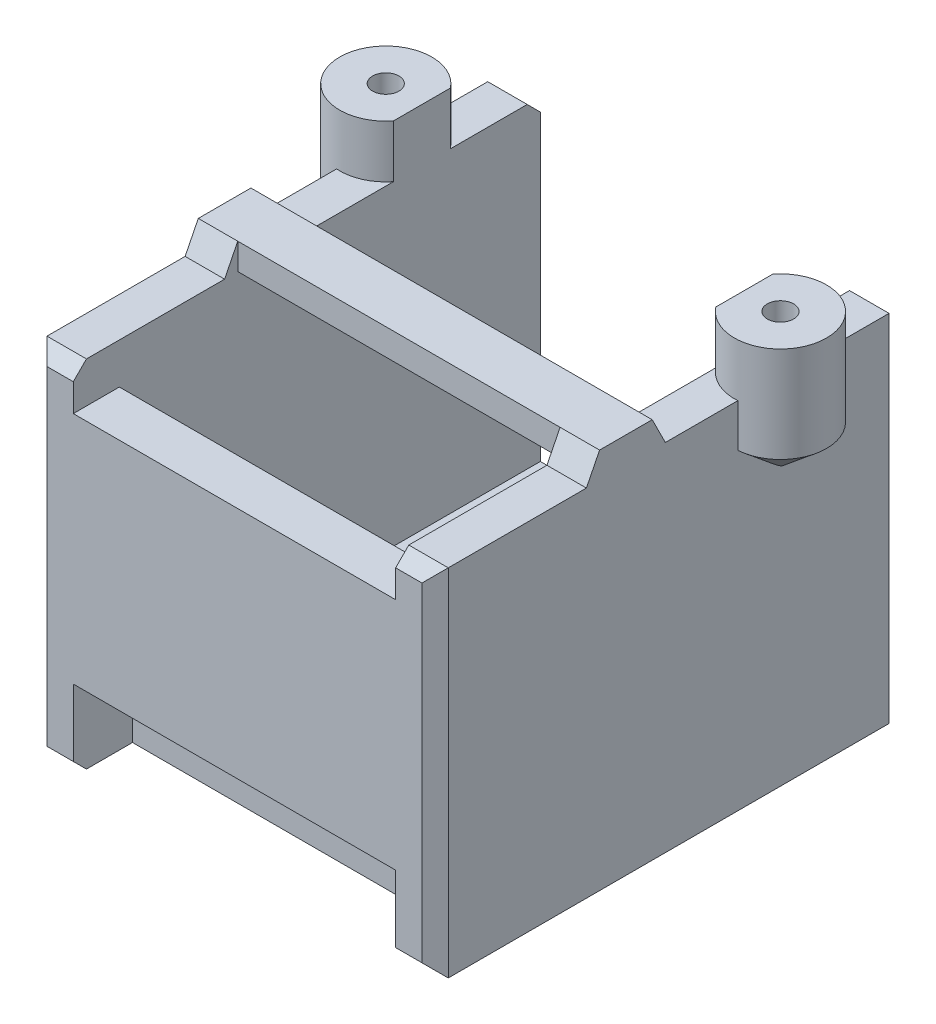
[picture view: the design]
ISO-10303-21;
HEADER;
FILE_DESCRIPTION(('STEP AP214'),'2;1');
FILE_NAME('part.step','',(''),(''),'','','');
FILE_SCHEMA(('AUTOMOTIVE_DESIGN { 1 0 10303 214 1 1 1 1 }'));
ENDSEC;
DATA;
#1=APPLICATION_CONTEXT('core data for automotive mechanical design processes');
#2=APPLICATION_PROTOCOL_DEFINITION('international standard','automotive_design',2000,#1);
#3=PRODUCT_CONTEXT('',#1,'mechanical');
#4=PRODUCT('Part','Part','',(#3));
#5=PRODUCT_RELATED_PRODUCT_CATEGORY('part','',(#4));
#6=PRODUCT_DEFINITION_FORMATION('','',#4);
#7=PRODUCT_DEFINITION_CONTEXT('part definition',#1,'design');
#8=PRODUCT_DEFINITION('design','',#6,#7);
#9=PRODUCT_DEFINITION_SHAPE('','',#8);
#10=(LENGTH_UNIT() NAMED_UNIT(*) SI_UNIT(.MILLI.,.METRE.));
#11=(NAMED_UNIT(*) PLANE_ANGLE_UNIT() SI_UNIT($,.RADIAN.));
#12=(NAMED_UNIT(*) SI_UNIT($,.STERADIAN.) SOLID_ANGLE_UNIT());
#13=UNCERTAINTY_MEASURE_WITH_UNIT(LENGTH_MEASURE(1.E-05),#10,'distance_accuracy_value','');
#14=(GEOMETRIC_REPRESENTATION_CONTEXT(3) GLOBAL_UNCERTAINTY_ASSIGNED_CONTEXT((#13)) GLOBAL_UNIT_ASSIGNED_CONTEXT((#10,
#11,#12)) REPRESENTATION_CONTEXT('',''));
#15=CARTESIAN_POINT('',(0.,0.,0.));
#16=DIRECTION('',(0.,0.,1.));
#17=DIRECTION('',(1.,0.,0.));
#18=AXIS2_PLACEMENT_3D('',#15,#16,#17);
#19=CARTESIAN_POINT('',(0.,12.,0.));
#20=DIRECTION('',(0.,1.,0.));
#21=DIRECTION('',(0.,0.,1.));
#22=AXIS2_PLACEMENT_3D('',#19,#20,#21);
#23=PLANE('',#22);
#24=DIRECTION('',(0.,0.,-1.));
#25=VECTOR('',#24,1.);
#26=CARTESIAN_POINT('',(15.25,12.,0.));
#27=LINE('',#26,#25);
#28=CARTESIAN_POINT('',(15.25,12.,19.));
#29=VERTEX_POINT('',#28);
#30=CARTESIAN_POINT('',(15.25,12.,8.5));
#31=VERTEX_POINT('',#30);
#32=EDGE_CURVE('E683',#29,#31,#27,.T.);
#33=ORIENTED_EDGE('',*,*,#32,.T.);
#34=DIRECTION('',(-1.,0.,0.));
#35=VECTOR('',#34,1.);
#36=CARTESIAN_POINT('',(0.,12.,8.5));
#37=LINE('',#36,#35);
#38=CARTESIAN_POINT('',(12.25,12.,8.5));
#39=VERTEX_POINT('',#38);
#40=EDGE_CURVE('E375',#31,#39,#37,.T.);
#41=ORIENTED_EDGE('',*,*,#40,.T.);
#42=DIRECTION('',(0.,0.,-1.));
#43=VECTOR('',#42,1.);
#44=CARTESIAN_POINT('',(12.25,12.,0.));
#45=LINE('',#44,#43);
#46=CARTESIAN_POINT('',(12.25,12.,19.));
#47=VERTEX_POINT('',#46);
#48=EDGE_CURVE('E681',#47,#39,#45,.T.);
#49=ORIENTED_EDGE('',*,*,#48,.F.);
#50=DIRECTION('',(1.,0.,0.));
#51=VECTOR('',#50,1.);
#52=CARTESIAN_POINT('',(15.25,12.,19.));
#53=LINE('',#52,#51);
#54=EDGE_CURVE('E450',#47,#29,#53,.T.);
#55=ORIENTED_EDGE('',*,*,#54,.T.);
#56=EDGE_LOOP('',(#33,#41,#49,#55));
#57=FACE_BOUND('',#56,.T.);
#58=ADVANCED_FACE('F41',(#57),#23,.T.);
#59=CARTESIAN_POINT('',(12.25,12.,2.5));
#60=VERTEX_POINT('',#59);
#61=CARTESIAN_POINT('',(12.25,12.,-4.33493649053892));
#62=VERTEX_POINT('',#61);
#63=EDGE_CURVE('E769',#60,#62,#45,.T.);
#64=ORIENTED_EDGE('',*,*,#63,.F.);
#65=DIRECTION('',(1.,0.,0.));
#66=VECTOR('',#65,1.);
#67=CARTESIAN_POINT('',(0.,12.,2.5));
#68=LINE('',#67,#66);
#69=CARTESIAN_POINT('',(15.25,12.,2.5));
#70=VERTEX_POINT('',#69);
#71=EDGE_CURVE('E402',#60,#70,#68,.T.);
#72=ORIENTED_EDGE('',*,*,#71,.T.);
#73=CARTESIAN_POINT('',(15.25,12.,-3.00893998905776));
#74=VERTEX_POINT('',#73);
#75=EDGE_CURVE('E367',#70,#74,#27,.T.);
#76=ORIENTED_EDGE('',*,*,#75,.T.);
#77=CARTESIAN_POINT('',(15.,12.,-6.5));
#78=DIRECTION('',(0.,1.,0.));
#79=DIRECTION('',(0.,0.,1.));
#80=AXIS2_PLACEMENT_3D('',#77,#78,#79);
#81=CIRCLE('',#80,3.5);
#82=EDGE_CURVE('E1433',#62,#74,#81,.T.);
#83=ORIENTED_EDGE('',*,*,#82,.F.);
#84=EDGE_LOOP('',(#64,#72,#76,#83));
#85=FACE_BOUND('',#84,.T.);
#86=ADVANCED_FACE('F651',(#85),#23,.T.);
#87=CARTESIAN_POINT('',(0.,12.,0.));
#88=DIRECTION('',(0.,1.,0.));
#89=DIRECTION('',(0.,0.,1.));
#90=AXIS2_PLACEMENT_3D('',#87,#88,#89);
#91=PLANE('',#90);
#92=DIRECTION('',(0.,0.,1.));
#93=VECTOR('',#92,1.);
#94=CARTESIAN_POINT('',(-12.25,12.,0.));
#95=LINE('',#94,#93);
#96=CARTESIAN_POINT('',(-12.25,12.,8.49999999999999));
#97=VERTEX_POINT('',#96);
#98=CARTESIAN_POINT('',(-12.25,12.,19.));
#99=VERTEX_POINT('',#98);
#100=EDGE_CURVE('E383',#97,#99,#95,.T.);
#101=ORIENTED_EDGE('',*,*,#100,.F.);
#102=DIRECTION('',(-1.,0.,0.));
#103=VECTOR('',#102,1.);
#104=CARTESIAN_POINT('',(0.,12.,8.49999999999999));
#105=LINE('',#104,#103);
#106=CARTESIAN_POINT('',(-15.25,12.,8.49999999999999));
#107=VERTEX_POINT('',#106);
#108=EDGE_CURVE('E388',#97,#107,#105,.T.);
#109=ORIENTED_EDGE('',*,*,#108,.T.);
#110=DIRECTION('',(0.,0.,1.));
#111=VECTOR('',#110,1.);
#112=CARTESIAN_POINT('',(-15.25,12.,0.));
#113=LINE('',#112,#111);
#114=CARTESIAN_POINT('',(-15.25,12.,19.));
#115=VERTEX_POINT('',#114);
#116=EDGE_CURVE('E325',#107,#115,#113,.T.);
#117=ORIENTED_EDGE('',*,*,#116,.T.);
#118=DIRECTION('',(1.,0.,0.));
#119=VECTOR('',#118,1.);
#120=CARTESIAN_POINT('',(-12.25,12.,19.));
#121=LINE('',#120,#119);
#122=EDGE_CURVE('E390',#115,#99,#121,.T.);
#123=ORIENTED_EDGE('',*,*,#122,.T.);
#124=EDGE_LOOP('',(#101,#109,#117,#123));
#125=FACE_BOUND('',#124,.T.);
#126=ADVANCED_FACE('F387',(#125),#91,.T.);
#127=CARTESIAN_POINT('',(-15.25,12.,-3.00893998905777));
#128=VERTEX_POINT('',#127);
#129=CARTESIAN_POINT('',(-15.25,12.,2.5));
#130=VERTEX_POINT('',#129);
#131=EDGE_CURVE('E712',#128,#130,#113,.T.);
#132=ORIENTED_EDGE('',*,*,#131,.T.);
#133=DIRECTION('',(1.,0.,0.));
#134=VECTOR('',#133,1.);
#135=CARTESIAN_POINT('',(0.,12.,2.5));
#136=LINE('',#135,#134);
#137=CARTESIAN_POINT('',(-12.25,12.,2.5));
#138=VERTEX_POINT('',#137);
#139=EDGE_CURVE('E400',#130,#138,#136,.T.);
#140=ORIENTED_EDGE('',*,*,#139,.T.);
#141=CARTESIAN_POINT('',(-12.25,12.,-4.33493649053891));
#142=VERTEX_POINT('',#141);
#143=EDGE_CURVE('E392',#142,#138,#95,.T.);
#144=ORIENTED_EDGE('',*,*,#143,.F.);
#145=CARTESIAN_POINT('',(-15.,12.,-6.5));
#146=DIRECTION('',(0.,1.,0.));
#147=DIRECTION('',(0.,0.,1.));
#148=AXIS2_PLACEMENT_3D('',#145,#146,#147);
#149=CIRCLE('',#148,3.5);
#150=EDGE_CURVE('E830',#128,#142,#149,.T.);
#151=ORIENTED_EDGE('',*,*,#150,.F.);
#152=EDGE_LOOP('',(#132,#140,#144,#151));
#153=FACE_BOUND('',#152,.T.);
#154=ADVANCED_FACE('F663',(#153),#91,.T.);
#155=CARTESIAN_POINT('',(15.25,12.,-9.99106001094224));
#156=VERTEX_POINT('',#155);
#157=CARTESIAN_POINT('',(15.25,12.,-14.5));
#158=VERTEX_POINT('',#157);
#159=EDGE_CURVE('E675',#156,#158,#27,.T.);
#160=ORIENTED_EDGE('',*,*,#159,.T.);
#161=DIRECTION('',(-1.,0.,0.));
#162=VECTOR('',#161,1.);
#163=CARTESIAN_POINT('',(12.25,12.,-14.5));
#164=LINE('',#163,#162);
#165=CARTESIAN_POINT('',(12.25,12.,-14.5));
#166=VERTEX_POINT('',#165);
#167=EDGE_CURVE('E472',#158,#166,#164,.T.);
#168=ORIENTED_EDGE('',*,*,#167,.T.);
#169=CARTESIAN_POINT('',(12.25,12.,-8.66506350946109));
#170=VERTEX_POINT('',#169);
#171=EDGE_CURVE('E766',#170,#166,#45,.T.);
#172=ORIENTED_EDGE('',*,*,#171,.F.);
#173=EDGE_CURVE('E679',#156,#170,#81,.T.);
#174=ORIENTED_EDGE('',*,*,#173,.F.);
#175=EDGE_LOOP('',(#160,#168,#172,#174));
#176=FACE_BOUND('',#175,.T.);
#177=ADVANCED_FACE('F654',(#176),#23,.T.);
#178=CARTESIAN_POINT('',(-12.25,12.,-14.5));
#179=VERTEX_POINT('',#178);
#180=CARTESIAN_POINT('',(-12.25,12.,-8.66506350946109));
#181=VERTEX_POINT('',#180);
#182=EDGE_CURVE('E395',#179,#181,#95,.T.);
#183=ORIENTED_EDGE('',*,*,#182,.F.);
#184=DIRECTION('',(-1.,0.,0.));
#185=VECTOR('',#184,1.);
#186=CARTESIAN_POINT('',(-15.25,12.,-14.5));
#187=LINE('',#186,#185);
#188=CARTESIAN_POINT('',(-15.25,12.,-14.5));
#189=VERTEX_POINT('',#188);
#190=EDGE_CURVE('E504',#179,#189,#187,.T.);
#191=ORIENTED_EDGE('',*,*,#190,.T.);
#192=CARTESIAN_POINT('',(-15.25,12.,-9.99106001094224));
#193=VERTEX_POINT('',#192);
#194=EDGE_CURVE('E709',#189,#193,#113,.T.);
#195=ORIENTED_EDGE('',*,*,#194,.T.);
#196=EDGE_CURVE('E836',#181,#193,#149,.T.);
#197=ORIENTED_EDGE('',*,*,#196,.F.);
#198=EDGE_LOOP('',(#183,#191,#195,#197));
#199=FACE_BOUND('',#198,.T.);
#200=ADVANCED_FACE('F662',(#199),#91,.T.);
#201=CARTESIAN_POINT('',(0.,8.9,15.5));
#202=DIRECTION('',(0.,0.,-1.));
#203=DIRECTION('',(-1.,0.,0.));
#204=AXIS2_PLACEMENT_3D('',#201,#202,#203);
#205=PLANE('',#204);
#206=DIRECTION('',(0.,-1.,0.));
#207=VECTOR('',#206,1.);
#208=CARTESIAN_POINT('',(12.25,8.9,15.5));
#209=LINE('',#208,#207);
#210=CARTESIAN_POINT('',(12.25,7.90000000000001,15.5));
#211=VERTEX_POINT('',#210);
#212=CARTESIAN_POINT('',(12.25,-7.9,15.5));
#213=VERTEX_POINT('',#212);
#214=EDGE_CURVE('E736',#211,#213,#209,.T.);
#215=ORIENTED_EDGE('',*,*,#214,.T.);
#216=DIRECTION('',(-1.,0.,0.));
#217=VECTOR('',#216,1.);
#218=CARTESIAN_POINT('',(-12.25,-7.9,15.5));
#219=LINE('',#218,#217);
#220=CARTESIAN_POINT('',(-12.25,-7.9,15.5));
#221=VERTEX_POINT('',#220);
#222=EDGE_CURVE('E417',#213,#221,#219,.T.);
#223=ORIENTED_EDGE('',*,*,#222,.T.);
#224=DIRECTION('',(0.,-1.,0.));
#225=VECTOR('',#224,1.);
#226=CARTESIAN_POINT('',(-12.25,8.9,15.5));
#227=LINE('',#226,#225);
#228=CARTESIAN_POINT('',(-12.25,7.90000000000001,15.5));
#229=VERTEX_POINT('',#228);
#230=EDGE_CURVE('E728',#229,#221,#227,.T.);
#231=ORIENTED_EDGE('',*,*,#230,.F.);
#232=DIRECTION('',(1.,0.,0.));
#233=VECTOR('',#232,1.);
#234=CARTESIAN_POINT('',(0.,7.90000000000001,15.5));
#235=LINE('',#234,#233);
#236=EDGE_CURVE('E419',#229,#211,#235,.T.);
#237=ORIENTED_EDGE('',*,*,#236,.T.);
#238=EDGE_LOOP('',(#215,#223,#231,#237));
#239=FACE_BOUND('',#238,.T.);
#240=ADVANCED_FACE('F669',(#239),#205,.T.);
#241=CARTESIAN_POINT('',(0.,8.9,20.));
#242=DIRECTION('',(0.,0.,-1.));
#243=DIRECTION('',(-1.,0.,0.));
#244=AXIS2_PLACEMENT_3D('',#241,#242,#243);
#245=PLANE('',#244);
#246=DIRECTION('',(0.,-1.,0.));
#247=VECTOR('',#246,1.);
#248=CARTESIAN_POINT('',(12.25,12.,20.));
#249=LINE('',#248,#247);
#250=CARTESIAN_POINT('',(12.25,-8.9,20.));
#251=VERTEX_POINT('',#250);
#252=CARTESIAN_POINT('',(12.25,-14.,20.));
#253=VERTEX_POINT('',#252);
#254=EDGE_CURVE('E700',#251,#253,#249,.T.);
#255=ORIENTED_EDGE('',*,*,#254,.T.);
#256=DIRECTION('',(1.,0.,0.));
#257=VECTOR('',#256,1.);
#258=CARTESIAN_POINT('',(0.,-14.,20.));
#259=LINE('',#258,#257);
#260=CARTESIAN_POINT('',(14.25,-14.,20.));
#261=VERTEX_POINT('',#260);
#262=EDGE_CURVE('E452',#253,#261,#259,.T.);
#263=ORIENTED_EDGE('',*,*,#262,.T.);
#264=DIRECTION('',(0.,1.,0.));
#265=VECTOR('',#264,1.);
#266=CARTESIAN_POINT('',(14.25,8.9,20.));
#267=LINE('',#266,#265);
#268=CARTESIAN_POINT('',(14.25,11.,20.));
#269=VERTEX_POINT('',#268);
#270=EDGE_CURVE('E455',#261,#269,#267,.T.);
#271=ORIENTED_EDGE('',*,*,#270,.T.);
#272=DIRECTION('',(-1.,0.,0.));
#273=VECTOR('',#272,1.);
#274=CARTESIAN_POINT('',(12.25,11.,20.));
#275=LINE('',#274,#273);
#276=CARTESIAN_POINT('',(12.25,11.,20.));
#277=VERTEX_POINT('',#276);
#278=EDGE_CURVE('E457',#269,#277,#275,.T.);
#279=ORIENTED_EDGE('',*,*,#278,.T.);
#280=CARTESIAN_POINT('',(12.25,8.9,20.));
#281=VERTEX_POINT('',#280);
#282=EDGE_CURVE('E703',#277,#281,#249,.T.);
#283=ORIENTED_EDGE('',*,*,#282,.T.);
#284=DIRECTION('',(1.,0.,0.));
#285=VECTOR('',#284,1.);
#286=CARTESIAN_POINT('',(0.,8.9,20.));
#287=LINE('',#286,#285);
#288=CARTESIAN_POINT('',(-12.25,8.9,20.));
#289=VERTEX_POINT('',#288);
#290=EDGE_CURVE('E725',#289,#281,#287,.T.);
#291=ORIENTED_EDGE('',*,*,#290,.F.);
#292=DIRECTION('',(0.,-1.,0.));
#293=VECTOR('',#292,1.);
#294=CARTESIAN_POINT('',(-12.25,12.,20.));
#295=LINE('',#294,#293);
#296=CARTESIAN_POINT('',(-12.25,11.,20.));
#297=VERTEX_POINT('',#296);
#298=EDGE_CURVE('E714',#297,#289,#295,.T.);
#299=ORIENTED_EDGE('',*,*,#298,.F.);
#300=DIRECTION('',(-1.,0.,0.));
#301=VECTOR('',#300,1.);
#302=CARTESIAN_POINT('',(-15.25,11.,20.));
#303=LINE('',#302,#301);
#304=CARTESIAN_POINT('',(-14.25,11.,20.));
#305=VERTEX_POINT('',#304);
#306=EDGE_CURVE('E464',#297,#305,#303,.T.);
#307=ORIENTED_EDGE('',*,*,#306,.T.);
#308=DIRECTION('',(0.,-1.,0.));
#309=VECTOR('',#308,1.);
#310=CARTESIAN_POINT('',(-14.25,8.9,20.));
#311=LINE('',#310,#309);
#312=CARTESIAN_POINT('',(-14.25,-14.,20.));
#313=VERTEX_POINT('',#312);
#314=EDGE_CURVE('E462',#305,#313,#311,.T.);
#315=ORIENTED_EDGE('',*,*,#314,.T.);
#316=DIRECTION('',(1.,0.,0.));
#317=VECTOR('',#316,1.);
#318=CARTESIAN_POINT('',(0.,-14.,20.));
#319=LINE('',#318,#317);
#320=CARTESIAN_POINT('',(-12.25,-14.,20.));
#321=VERTEX_POINT('',#320);
#322=EDGE_CURVE('E459',#313,#321,#319,.T.);
#323=ORIENTED_EDGE('',*,*,#322,.T.);
#324=CARTESIAN_POINT('',(-12.25,-8.9,20.));
#325=VERTEX_POINT('',#324);
#326=EDGE_CURVE('E711',#325,#321,#295,.T.);
#327=ORIENTED_EDGE('',*,*,#326,.F.);
#328=DIRECTION('',(1.,0.,0.));
#329=VECTOR('',#328,1.);
#330=CARTESIAN_POINT('',(0.,-8.9,20.));
#331=LINE('',#330,#329);
#332=EDGE_CURVE('E723',#325,#251,#331,.T.);
#333=ORIENTED_EDGE('',*,*,#332,.T.);
#334=EDGE_LOOP('',(#255,#263,#271,#279,#283,#291,#299,#307,#315,#323,#327,#333));
#335=FACE_BOUND('',#334,.T.);
#336=ADVANCED_FACE('F865',(#335),#245,.F.);
#337=CARTESIAN_POINT('',(0.,8.9,0.));
#338=DIRECTION('',(0.,1.,0.));
#339=DIRECTION('',(0.,0.,1.));
#340=AXIS2_PLACEMENT_3D('',#337,#338,#339);
#341=PLANE('',#340);
#342=DIRECTION('',(0.,0.,1.));
#343=VECTOR('',#342,1.);
#344=CARTESIAN_POINT('',(12.25,8.9,0.));
#345=LINE('',#344,#343);
#346=CARTESIAN_POINT('',(12.25,8.9,16.5));
#347=VERTEX_POINT('',#346);
#348=EDGE_CURVE('E720',#347,#281,#345,.T.);
#349=ORIENTED_EDGE('',*,*,#348,.F.);
#350=DIRECTION('',(-1.,0.,0.));
#351=VECTOR('',#350,1.);
#352=CARTESIAN_POINT('',(0.,8.9,16.5));
#353=LINE('',#352,#351);
#354=CARTESIAN_POINT('',(-12.25,8.9,16.5));
#355=VERTEX_POINT('',#354);
#356=EDGE_CURVE('E415',#347,#355,#353,.T.);
#357=ORIENTED_EDGE('',*,*,#356,.T.);
#358=DIRECTION('',(0.,0.,1.));
#359=VECTOR('',#358,1.);
#360=CARTESIAN_POINT('',(-12.25,8.9,0.));
#361=LINE('',#360,#359);
#362=EDGE_CURVE('E722',#355,#289,#361,.T.);
#363=ORIENTED_EDGE('',*,*,#362,.T.);
#364=ORIENTED_EDGE('',*,*,#290,.T.);
#365=EDGE_LOOP('',(#349,#357,#363,#364));
#366=FACE_BOUND('',#365,.T.);
#367=ADVANCED_FACE('F883',(#366),#341,.T.);
#368=CARTESIAN_POINT('',(0.,-8.9,0.));
#369=DIRECTION('',(0.,1.,0.));
#370=DIRECTION('',(0.,0.,1.));
#371=AXIS2_PLACEMENT_3D('',#368,#369,#370);
#372=PLANE('',#371);
#373=DIRECTION('',(0.,0.,1.));
#374=VECTOR('',#373,1.);
#375=CARTESIAN_POINT('',(-12.25,-8.9,0.));
#376=LINE('',#375,#374);
#377=CARTESIAN_POINT('',(-12.25,-8.9,16.5));
#378=VERTEX_POINT('',#377);
#379=EDGE_CURVE('E730',#378,#325,#376,.T.);
#380=ORIENTED_EDGE('',*,*,#379,.F.);
#381=DIRECTION('',(1.,0.,0.));
#382=VECTOR('',#381,1.);
#383=CARTESIAN_POINT('',(12.25,-8.9,16.5));
#384=LINE('',#383,#382);
#385=CARTESIAN_POINT('',(12.25,-8.9,16.5));
#386=VERTEX_POINT('',#385);
#387=EDGE_CURVE('E422',#378,#386,#384,.T.);
#388=ORIENTED_EDGE('',*,*,#387,.T.);
#389=DIRECTION('',(0.,0.,1.));
#390=VECTOR('',#389,1.);
#391=CARTESIAN_POINT('',(12.25,-8.9,0.));
#392=LINE('',#391,#390);
#393=EDGE_CURVE('E719',#386,#251,#392,.T.);
#394=ORIENTED_EDGE('',*,*,#393,.T.);
#395=ORIENTED_EDGE('',*,*,#332,.F.);
#396=EDGE_LOOP('',(#380,#388,#394,#395));
#397=FACE_BOUND('',#396,.T.);
#398=ADVANCED_FACE('F872',(#397),#372,.F.);
#399=CARTESIAN_POINT('',(-12.25,12.,0.));
#400=DIRECTION('',(1.,0.,0.));
#401=DIRECTION('',(0.,0.,-1.));
#402=AXIS2_PLACEMENT_3D('',#399,#400,#401);
#403=PLANE('',#402);
#404=DIRECTION('',(0.,-1.,0.));
#405=VECTOR('',#404,1.);
#406=CARTESIAN_POINT('',(-12.25,12.,-15.5));
#407=LINE('',#406,#405);
#408=CARTESIAN_POINT('',(-12.25,11.,-15.5));
#409=VERTEX_POINT('',#408);
#410=CARTESIAN_POINT('',(-12.25,-12.,-15.5));
#411=VERTEX_POINT('',#410);
#412=EDGE_CURVE('E717',#409,#411,#407,.T.);
#413=ORIENTED_EDGE('',*,*,#412,.F.);
#414=DIRECTION('',(0.,0.707106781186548,0.707106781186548));
#415=VECTOR('',#414,1.);
#416=CARTESIAN_POINT('',(-12.25,19.25,-7.25));
#417=LINE('',#416,#415);
#418=EDGE_CURVE('E488',#409,#179,#417,.T.);
#419=ORIENTED_EDGE('',*,*,#418,.T.);
#420=ORIENTED_EDGE('',*,*,#182,.T.);
#421=DIRECTION('',(0.,-1.,0.));
#422=VECTOR('',#421,1.);
#423=CARTESIAN_POINT('',(-12.25,16.,-8.66506350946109));
#424=LINE('',#423,#422);
#425=CARTESIAN_POINT('',(-12.25,16.,-8.66506350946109));
#426=VERTEX_POINT('',#425);
#427=EDGE_CURVE('E848',#426,#181,#424,.T.);
#428=ORIENTED_EDGE('',*,*,#427,.F.);
#429=DIRECTION('',(0.,0.,1.));
#430=VECTOR('',#429,1.);
#431=CARTESIAN_POINT('',(-12.25,16.,0.));
#432=LINE('',#431,#430);
#433=CARTESIAN_POINT('',(-12.25,16.,-4.33493649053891));
#434=VERTEX_POINT('',#433);
#435=EDGE_CURVE('E846',#426,#434,#432,.T.);
#436=ORIENTED_EDGE('',*,*,#435,.T.);
#437=DIRECTION('',(0.,-1.,0.));
#438=VECTOR('',#437,1.);
#439=CARTESIAN_POINT('',(-12.25,16.,-4.33493649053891));
#440=LINE('',#439,#438);
#441=EDGE_CURVE('E810',#434,#142,#440,.T.);
#442=ORIENTED_EDGE('',*,*,#441,.T.);
#443=ORIENTED_EDGE('',*,*,#143,.T.);
#444=DIRECTION('',(0.,0.894427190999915,0.447213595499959));
#445=VECTOR('',#444,1.);
#446=CARTESIAN_POINT('',(-12.25,14.,3.5));
#447=LINE('',#446,#445);
#448=CARTESIAN_POINT('',(-12.25,14.,3.5));
#449=VERTEX_POINT('',#448);
#450=EDGE_CURVE('E373',#138,#449,#447,.T.);
#451=ORIENTED_EDGE('',*,*,#450,.T.);
#452=DIRECTION('',(0.,1.,0.));
#453=VECTOR('',#452,1.);
#454=CARTESIAN_POINT('',(-12.25,14.,3.5));
#455=LINE('',#454,#453);
#456=CARTESIAN_POINT('',(-12.25,12.,3.5));
#457=VERTEX_POINT('',#456);
#458=EDGE_CURVE('E64',#457,#449,#455,.T.);
#459=ORIENTED_EDGE('',*,*,#458,.F.);
#460=DIRECTION('',(0.,0.,1.));
#461=VECTOR('',#460,1.);
#462=CARTESIAN_POINT('',(-12.25,12.,0.));
#463=LINE('',#462,#461);
#464=CARTESIAN_POINT('',(-12.25,12.,7.5));
#465=VERTEX_POINT('',#464);
#466=EDGE_CURVE('E432',#457,#465,#463,.T.);
#467=ORIENTED_EDGE('',*,*,#466,.T.);
#468=DIRECTION('',(0.,-1.,0.));
#469=VECTOR('',#468,1.);
#470=CARTESIAN_POINT('',(-12.25,14.,7.5));
#471=LINE('',#470,#469);
#472=CARTESIAN_POINT('',(-12.25,14.,7.5));
#473=VERTEX_POINT('',#472);
#474=EDGE_CURVE('E385',#473,#465,#471,.T.);
#475=ORIENTED_EDGE('',*,*,#474,.F.);
#476=DIRECTION('',(0.,-0.894427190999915,0.44721359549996));
#477=VECTOR('',#476,1.);
#478=CARTESIAN_POINT('',(-12.25,14.,7.5));
#479=LINE('',#478,#477);
#480=EDGE_CURVE('E329',#473,#97,#479,.T.);
#481=ORIENTED_EDGE('',*,*,#480,.T.);
#482=ORIENTED_EDGE('',*,*,#100,.T.);
#483=DIRECTION('',(0.,-0.707106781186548,0.707106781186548));
#484=VECTOR('',#483,1.);
#485=CARTESIAN_POINT('',(-12.25,21.5,9.5));
#486=LINE('',#485,#484);
#487=EDGE_CURVE('E492',#99,#297,#486,.T.);
#488=ORIENTED_EDGE('',*,*,#487,.T.);
#489=ORIENTED_EDGE('',*,*,#298,.T.);
#490=ORIENTED_EDGE('',*,*,#362,.F.);
#491=DIRECTION('',(0.,0.707106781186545,0.70710678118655));
#492=VECTOR('',#491,1.);
#493=CARTESIAN_POINT('',(-12.25,7.90000000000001,15.5));
#494=LINE('',#493,#492);
#495=EDGE_CURVE('E407',#355,#229,#494,.F.);
#496=ORIENTED_EDGE('',*,*,#495,.T.);
#497=ORIENTED_EDGE('',*,*,#230,.T.);
#498=DIRECTION('',(0.,-0.70710678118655,0.707106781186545));
#499=VECTOR('',#498,1.);
#500=CARTESIAN_POINT('',(-12.25,-8.9,16.5));
#501=LINE('',#500,#499);
#502=EDGE_CURVE('E411',#221,#378,#501,.T.);
#503=ORIENTED_EDGE('',*,*,#502,.T.);
#504=ORIENTED_EDGE('',*,*,#379,.T.);
#505=ORIENTED_EDGE('',*,*,#326,.T.);
#506=DIRECTION('',(0.,0.707106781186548,0.707106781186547));
#507=VECTOR('',#506,1.);
#508=CARTESIAN_POINT('',(-12.25,-11.,23.));
#509=LINE('',#508,#507);
#510=CARTESIAN_POINT('',(-12.25,-15.,19.));
#511=VERTEX_POINT('',#510);
#512=EDGE_CURVE('E490',#321,#511,#509,.F.);
#513=ORIENTED_EDGE('',*,*,#512,.T.);
#514=DIRECTION('',(0.,0.,1.));
#515=VECTOR('',#514,1.);
#516=CARTESIAN_POINT('',(-12.25,-15.,0.));
#517=LINE('',#516,#515);
#518=CARTESIAN_POINT('',(-12.25,-15.,15.5));
#519=VERTEX_POINT('',#518);
#520=EDGE_CURVE('E813',#519,#511,#517,.T.);
#521=ORIENTED_EDGE('',*,*,#520,.F.);
#522=DIRECTION('',(0.,1.,0.));
#523=VECTOR('',#522,1.);
#524=CARTESIAN_POINT('',(-12.25,-15.,15.5));
#525=LINE('',#524,#523);
#526=CARTESIAN_POINT('',(-12.25,-12.,15.5));
#527=VERTEX_POINT('',#526);
#528=EDGE_CURVE('E802',#519,#527,#525,.T.);
#529=ORIENTED_EDGE('',*,*,#528,.T.);
#530=DIRECTION('',(0.,0.,1.));
#531=VECTOR('',#530,1.);
#532=CARTESIAN_POINT('',(-12.25,-12.,0.));
#533=LINE('',#532,#531);
#534=EDGE_CURVE('E393',#411,#527,#533,.T.);
#535=ORIENTED_EDGE('',*,*,#534,.F.);
#536=EDGE_LOOP('',(#413,#419,#420,#428,#436,#442,#443,#451,#459,#467,#475,#481,#482,#488,#489,
#490,#496,#497,#503,#504,#505,#513,#521,#529,#535));
#537=FACE_BOUND('',#536,.T.);
#538=ADVANCED_FACE('F382',(#537),#403,.T.);
#539=CARTESIAN_POINT('',(0.,12.,-15.5));
#540=DIRECTION('',(0.,0.,1.));
#541=DIRECTION('',(1.,0.,0.));
#542=AXIS2_PLACEMENT_3D('',#539,#540,#541);
#543=PLANE('',#542);
#544=DIRECTION('',(0.,1.,0.));
#545=VECTOR('',#544,1.);
#546=CARTESIAN_POINT('',(-14.25,12.,-15.5));
#547=LINE('',#546,#545);
#548=CARTESIAN_POINT('',(-14.25,-14.,-15.5));
#549=VERTEX_POINT('',#548);
#550=CARTESIAN_POINT('',(-14.25,11.,-15.5));
#551=VERTEX_POINT('',#550);
#552=EDGE_CURVE('E496',#549,#551,#547,.T.);
#553=ORIENTED_EDGE('',*,*,#552,.T.);
#554=DIRECTION('',(1.,0.,0.));
#555=VECTOR('',#554,1.);
#556=CARTESIAN_POINT('',(-12.25,11.,-15.5));
#557=LINE('',#556,#555);
#558=EDGE_CURVE('E494',#551,#409,#557,.T.);
#559=ORIENTED_EDGE('',*,*,#558,.T.);
#560=ORIENTED_EDGE('',*,*,#412,.T.);
#561=DIRECTION('',(1.,0.,0.));
#562=VECTOR('',#561,1.);
#563=CARTESIAN_POINT('',(0.,-12.,-15.5));
#564=LINE('',#563,#562);
#565=CARTESIAN_POINT('',(12.25,-12.,-15.5));
#566=VERTEX_POINT('',#565);
#567=EDGE_CURVE('E698',#411,#566,#564,.T.);
#568=ORIENTED_EDGE('',*,*,#567,.T.);
#569=DIRECTION('',(0.,-1.,0.));
#570=VECTOR('',#569,1.);
#571=CARTESIAN_POINT('',(12.25,12.,-15.5));
#572=LINE('',#571,#570);
#573=CARTESIAN_POINT('',(12.25,11.,-15.5));
#574=VERTEX_POINT('',#573);
#575=EDGE_CURVE('E696',#574,#566,#572,.T.);
#576=ORIENTED_EDGE('',*,*,#575,.F.);
#577=DIRECTION('',(1.,0.,0.));
#578=VECTOR('',#577,1.);
#579=CARTESIAN_POINT('',(15.25,11.,-15.5));
#580=LINE('',#579,#578);
#581=CARTESIAN_POINT('',(14.25,11.,-15.5));
#582=VERTEX_POINT('',#581);
#583=EDGE_CURVE('E502',#574,#582,#580,.T.);
#584=ORIENTED_EDGE('',*,*,#583,.T.);
#585=DIRECTION('',(0.,-1.,0.));
#586=VECTOR('',#585,1.);
#587=CARTESIAN_POINT('',(14.25,12.,-15.5));
#588=LINE('',#587,#586);
#589=CARTESIAN_POINT('',(14.25,-14.,-15.5));
#590=VERTEX_POINT('',#589);
#591=EDGE_CURVE('E500',#582,#590,#588,.T.);
#592=ORIENTED_EDGE('',*,*,#591,.T.);
#593=DIRECTION('',(-1.,0.,0.));
#594=VECTOR('',#593,1.);
#595=CARTESIAN_POINT('',(0.,-14.,-15.5));
#596=LINE('',#595,#594);
#597=EDGE_CURVE('E498',#590,#549,#596,.T.);
#598=ORIENTED_EDGE('',*,*,#597,.T.);
#599=EDGE_LOOP('',(#553,#559,#560,#568,#576,#584,#592,#598));
#600=FACE_BOUND('',#599,.T.);
#601=ADVANCED_FACE('F692',(#600),#543,.F.);
#602=CARTESIAN_POINT('',(-15.25,12.,0.));
#603=DIRECTION('',(1.,0.,0.));
#604=DIRECTION('',(0.,0.,-1.));
#605=AXIS2_PLACEMENT_3D('',#602,#603,#604);
#606=PLANE('',#605);
#607=ORIENTED_EDGE('',*,*,#194,.F.);
#608=DIRECTION('',(0.,-1.,0.));
#609=VECTOR('',#608,1.);
#610=CARTESIAN_POINT('',(-15.25,12.,-14.5));
#611=LINE('',#610,#609);
#612=CARTESIAN_POINT('',(-15.25,-15.,-14.5));
#613=VERTEX_POINT('',#612);
#614=EDGE_CURVE('E484',#189,#613,#611,.T.);
#615=ORIENTED_EDGE('',*,*,#614,.T.);
#616=DIRECTION('',(0.,0.,1.));
#617=VECTOR('',#616,1.);
#618=CARTESIAN_POINT('',(-15.25,-15.,0.));
#619=LINE('',#618,#617);
#620=CARTESIAN_POINT('',(-15.25,-15.,19.));
#621=VERTEX_POINT('',#620);
#622=EDGE_CURVE('E804',#613,#621,#619,.T.);
#623=ORIENTED_EDGE('',*,*,#622,.T.);
#624=DIRECTION('',(0.,1.,0.));
#625=VECTOR('',#624,1.);
#626=CARTESIAN_POINT('',(-15.25,12.,19.));
#627=LINE('',#626,#625);
#628=EDGE_CURVE('E486',#621,#115,#627,.T.);
#629=ORIENTED_EDGE('',*,*,#628,.T.);
#630=ORIENTED_EDGE('',*,*,#116,.F.);
#631=DIRECTION('',(0.,0.894427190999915,-0.44721359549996));
#632=VECTOR('',#631,1.);
#633=CARTESIAN_POINT('',(-15.25,15.4,6.79999999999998));
#634=LINE('',#633,#632);
#635=CARTESIAN_POINT('',(-15.25,14.,7.5));
#636=VERTEX_POINT('',#635);
#637=EDGE_CURVE('E319',#107,#636,#634,.T.);
#638=ORIENTED_EDGE('',*,*,#637,.T.);
#639=DIRECTION('',(0.,0.,1.));
#640=VECTOR('',#639,1.);
#641=CARTESIAN_POINT('',(-15.25,14.,3.5));
#642=LINE('',#641,#640);
#643=CARTESIAN_POINT('',(-15.25,14.,3.5));
#644=VERTEX_POINT('',#643);
#645=EDGE_CURVE('E323',#644,#636,#642,.T.);
#646=ORIENTED_EDGE('',*,*,#645,.F.);
#647=DIRECTION('',(0.,-0.894427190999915,-0.447213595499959));
#648=VECTOR('',#647,1.);
#649=CARTESIAN_POINT('',(-15.25,11.,2.));
#650=LINE('',#649,#648);
#651=EDGE_CURVE('E370',#644,#130,#650,.T.);
#652=ORIENTED_EDGE('',*,*,#651,.T.);
#653=ORIENTED_EDGE('',*,*,#131,.F.);
#654=DIRECTION('',(0.,1.,0.));
#655=VECTOR('',#654,1.);
#656=CARTESIAN_POINT('',(-15.25,6.,-3.00893998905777));
#657=LINE('',#656,#655);
#658=CARTESIAN_POINT('',(-15.25,8.72707380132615,-3.00893998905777));
#659=VERTEX_POINT('',#658);
#660=EDGE_CURVE('E820',#659,#128,#657,.T.);
#661=ORIENTED_EDGE('',*,*,#660,.F.);
#662=CARTESIAN_POINT('',(-15.25,8.72707380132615,-3.00893998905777));
#663=CARTESIAN_POINT('',(-15.25,8.62392002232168,-3.13219135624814));
#664=CARTESIAN_POINT('',(-15.25,8.52078014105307,-3.25545436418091));
#665=CARTESIAN_POINT('',(-15.25,8.31453732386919,-3.50203064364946));
#666=CARTESIAN_POINT('',(-15.25,8.211434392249,-3.62534391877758));
#667=CARTESIAN_POINT('',(-15.25,8.00510236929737,-3.8722538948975));
#668=CARTESIAN_POINT('',(-15.25,7.90187339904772,-3.99585069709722));
#669=CARTESIAN_POINT('',(-15.25,7.69552650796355,-4.24311785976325));
#670=CARTESIAN_POINT('',(-15.25,7.59240857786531,-4.36678821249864));
#671=CARTESIAN_POINT('',(-15.25,7.3808709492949,-4.62082858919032));
#672=CARTESIAN_POINT('',(-15.25,7.2724601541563,-4.75120603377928));
#673=CARTESIAN_POINT('',(-15.25,7.11009050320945,-4.94700867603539));
#674=CARTESIAN_POINT('',(-15.25,7.05600055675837,-5.01232511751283));
#675=CARTESIAN_POINT('',(-15.25,6.94795351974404,-5.14306388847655));
#676=CARTESIAN_POINT('',(-15.25,6.89399642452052,-5.20848621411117));
#677=CARTESIAN_POINT('',(-15.25,6.78635205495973,-5.33940994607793));
#678=CARTESIAN_POINT('',(-15.25,6.73266452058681,-5.40491113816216));
#679=CARTESIAN_POINT('',(-15.25,6.62561682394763,-5.53619472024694));
#680=CARTESIAN_POINT('',(-15.25,6.57225670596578,-5.60197714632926));
#681=CARTESIAN_POINT('',(-15.25,6.46615601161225,-5.73398627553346));
#682=CARTESIAN_POINT('',(-15.25,6.41341512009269,-5.8002127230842));
#683=CARTESIAN_POINT('',(-15.25,6.33529954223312,-5.90031938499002));
#684=CARTESIAN_POINT('',(-15.25,6.30942971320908,-5.93381244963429));
#685=CARTESIAN_POINT('',(-15.25,6.25823113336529,-6.00120861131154));
#686=CARTESIAN_POINT('',(-15.25,6.2329023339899,-6.03511167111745));
#687=CARTESIAN_POINT('',(-15.25,6.19506261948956,-6.08726153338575));
#688=CARTESIAN_POINT('',(-15.25,6.18220496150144,-6.10525604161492));
#689=CARTESIAN_POINT('',(-15.25,6.15685880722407,-6.14150993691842));
#690=CARTESIAN_POINT('',(-15.25,6.1443703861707,-6.15976937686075));
#691=CARTESIAN_POINT('',(-15.25,6.11989409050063,-6.19670581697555));
#692=CARTESIAN_POINT('',(-15.25,6.10790790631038,-6.21538394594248));
#693=CARTESIAN_POINT('',(-15.25,6.08477030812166,-6.25324746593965));
#694=CARTESIAN_POINT('',(-15.25,6.07361856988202,-6.27243265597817));
#695=CARTESIAN_POINT('',(-15.25,6.05119713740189,-6.3141895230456));
#696=CARTESIAN_POINT('',(-15.25,6.04011886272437,-6.33686615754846));
#697=CARTESIAN_POINT('',(-15.25,6.02109333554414,-6.38336309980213));
#698=CARTESIAN_POINT('',(-15.25,6.01311750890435,-6.40717058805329));
#699=CARTESIAN_POINT('',(-15.25,6.00524561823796,-6.44273251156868));
#700=CARTESIAN_POINT('',(-15.25,6.00331329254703,-6.45402691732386));
#701=CARTESIAN_POINT('',(-15.25,6.00067414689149,-6.47687384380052));
#702=CARTESIAN_POINT('',(-15.25,5.99998021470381,-6.48842782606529));
#703=CARTESIAN_POINT('',(-15.25,5.99999999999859,-6.49999999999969));
#704=B_SPLINE_CURVE_WITH_KNOTS('',3,(#662,#663,#664,#665,#666,#667,#668,#669,#670,#671,#672,
#673,#674,#675,#676,#677,#678,#679,#680,#681,#682,#683,#684,#685,#686,#687,#688,#689,#690,#691,
#692,#693,#694,#695,#696,#697,#698,#699,#700,#701,#702,#703),.UNSPECIFIED.,.F.,.F.,(4,2,2,2,2,2,
2,2,2,2,2,2,2,2,2,2,2,2,2,2,4),(0.,0.482166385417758,0.964377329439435,1.44748339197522,
1.93054542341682,2.43923021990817,2.69364635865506,2.94805344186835,3.20212889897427,
3.45623799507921,3.71021160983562,3.83717102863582,3.96411900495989,4.03046414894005,
4.09682271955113,4.16338914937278,4.22992957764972,4.3055468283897,4.38045013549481,
4.41476128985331,4.44942747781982),.UNSPECIFIED.);
#705=CARTESIAN_POINT('',(-15.25,6.,-6.5));
#706=VERTEX_POINT('',#705);
#707=EDGE_CURVE('E515',#659,#706,#704,.T.);
#708=ORIENTED_EDGE('',*,*,#707,.T.);
#709=CARTESIAN_POINT('',(-15.25,6.,-6.5));
#710=CARTESIAN_POINT('',(-15.25,5.99999159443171,-6.50902905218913));
#711=CARTESIAN_POINT('',(-15.25,6.00041027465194,-6.5180528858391));
#712=CARTESIAN_POINT('',(-15.25,6.00203509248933,-6.53600980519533));
#713=CARTESIAN_POINT('',(-15.25,6.00323945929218,-6.54494304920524));
#714=CARTESIAN_POINT('',(-15.25,6.00633905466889,-6.56250714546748));
#715=CARTESIAN_POINT('',(-15.25,6.00822039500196,-6.57114050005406));
#716=CARTESIAN_POINT('',(-15.25,6.01258310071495,-6.58825622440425));
#717=CARTESIAN_POINT('',(-15.25,6.01506474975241,-6.59673852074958));
#718=CARTESIAN_POINT('',(-15.25,6.02495561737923,-6.62715653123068));
#719=CARTESIAN_POINT('',(-15.25,6.03383174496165,-6.64861271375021));
#720=CARTESIAN_POINT('',(-15.25,6.05359866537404,-6.69058075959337));
#721=CARTESIAN_POINT('',(-15.25,6.0644946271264,-6.71109002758));
#722=CARTESIAN_POINT('',(-15.25,6.08771923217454,-6.75184401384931));
#723=CARTESIAN_POINT('',(-15.25,6.10007310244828,-6.7720741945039));
#724=CARTESIAN_POINT('',(-15.25,6.125532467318,-6.81201082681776));
#725=CARTESIAN_POINT('',(-15.25,6.13863695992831,-6.83171792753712));
#726=CARTESIAN_POINT('',(-15.25,6.16737136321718,-6.87375053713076));
#727=CARTESIAN_POINT('',(-15.25,6.18308290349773,-6.89601996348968));
#728=CARTESIAN_POINT('',(-15.25,6.21493831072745,-6.9402483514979));
#729=CARTESIAN_POINT('',(-15.25,6.23108221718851,-6.96220728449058));
#730=CARTESIAN_POINT('',(-15.25,6.2799566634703,-7.02777228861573));
#731=CARTESIAN_POINT('',(-15.25,6.3131210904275,-7.07105402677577));
#732=CARTESIAN_POINT('',(-15.25,6.38008386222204,-7.15720466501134));
#733=CARTESIAN_POINT('',(-15.25,6.41388293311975,-7.20007299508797));
#734=CARTESIAN_POINT('',(-15.25,6.4818345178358,-7.28551654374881));
#735=CARTESIAN_POINT('',(-15.25,6.5159869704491,-7.32809181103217));
#736=CARTESIAN_POINT('',(-15.25,6.61784330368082,-7.45439290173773));
#737=CARTESIAN_POINT('',(-15.25,6.6858669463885,-7.53786027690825));
#738=CARTESIAN_POINT('',(-15.25,6.822281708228,-7.70441052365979));
#739=CARTESIAN_POINT('',(-15.25,6.8906725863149,-7.78749359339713));
#740=CARTESIAN_POINT('',(-15.25,7.10411651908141,-8.04608226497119));
#741=CARTESIAN_POINT('',(-15.25,7.24955710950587,-8.22126780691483));
#742=CARTESIAN_POINT('',(-15.25,7.54083834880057,-8.57137946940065));
#743=CARTESIAN_POINT('',(-15.25,7.68667908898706,-8.7463055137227));
#744=CARTESIAN_POINT('',(-15.25,7.98156720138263,-9.09961364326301));
#745=CARTESIAN_POINT('',(-15.25,8.13061853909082,-9.27799242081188));
#746=CARTESIAN_POINT('',(-15.25,8.42879865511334,-9.63460576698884));
#747=CARTESIAN_POINT('',(-15.25,8.57792740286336,-9.81284036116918));
#748=CARTESIAN_POINT('',(-15.25,8.72707380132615,-9.99106001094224));
#749=B_SPLINE_CURVE_WITH_KNOTS('',3,(#709,#710,#711,#712,#713,#714,#715,#716,#717,#718,#719,
#720,#721,#722,#723,#724,#725,#726,#727,#728,#729,#730,#731,#732,#733,#734,#735,#736,#737,#738,
#739,#740,#741,#742,#743,#744,#745,#746,#747,#748),.UNSPECIFIED.,.F.,.F.,(4,2,2,2,2,2,2,2,2,2,2,
2,2,2,2,2,2,2,2,4),(0.,0.0270691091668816,0.0540774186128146,0.0805605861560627,
0.107056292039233,0.176499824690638,0.246123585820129,0.317205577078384,0.388194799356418,
0.469948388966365,0.551709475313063,0.71527765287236,0.87904598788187,1.04278641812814,
1.36580975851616,1.6886421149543,2.3717112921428,3.05495205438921,3.75231668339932,
4.44949840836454),.UNSPECIFIED.);
#750=CARTESIAN_POINT('',(-15.25,8.72707380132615,-9.99106001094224));
#751=VERTEX_POINT('',#750);
#752=EDGE_CURVE('E507',#706,#751,#749,.T.);
#753=ORIENTED_EDGE('',*,*,#752,.T.);
#754=DIRECTION('',(0.,1.,0.));
#755=VECTOR('',#754,1.);
#756=CARTESIAN_POINT('',(-15.25,6.,-9.99106001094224));
#757=LINE('',#756,#755);
#758=EDGE_CURVE('E771',#751,#193,#757,.T.);
#759=ORIENTED_EDGE('',*,*,#758,.T.);
#760=EDGE_LOOP('',(#607,#615,#623,#629,#630,#638,#646,#652,#653,#661,#708,#753,#759));
#761=FACE_BOUND('',#760,.T.);
#762=ADVANCED_FACE('F322',(#761),#606,.F.);
#763=CARTESIAN_POINT('',(12.25,12.,0.));
#764=DIRECTION('',(-1.,0.,0.));
#765=DIRECTION('',(0.,0.,1.));
#766=AXIS2_PLACEMENT_3D('',#763,#764,#765);
#767=PLANE('',#766);
#768=ORIENTED_EDGE('',*,*,#171,.T.);
#769=DIRECTION('',(0.,-0.707106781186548,-0.707106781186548));
#770=VECTOR('',#769,1.);
#771=CARTESIAN_POINT('',(12.25,19.25,-7.25));
#772=LINE('',#771,#770);
#773=EDGE_CURVE('E466',#166,#574,#772,.T.);
#774=ORIENTED_EDGE('',*,*,#773,.T.);
#775=ORIENTED_EDGE('',*,*,#575,.T.);
#776=DIRECTION('',(0.,0.,-1.));
#777=VECTOR('',#776,1.);
#778=CARTESIAN_POINT('',(12.25,-12.,0.));
#779=LINE('',#778,#777);
#780=CARTESIAN_POINT('',(12.25,-12.,15.5));
#781=VERTEX_POINT('',#780);
#782=EDGE_CURVE('E706',#781,#566,#779,.T.);
#783=ORIENTED_EDGE('',*,*,#782,.F.);
#784=DIRECTION('',(0.,1.,0.));
#785=VECTOR('',#784,1.);
#786=CARTESIAN_POINT('',(12.25,-15.,15.5));
#787=LINE('',#786,#785);
#788=CARTESIAN_POINT('',(12.25,-15.,15.5));
#789=VERTEX_POINT('',#788);
#790=EDGE_CURVE('E798',#789,#781,#787,.T.);
#791=ORIENTED_EDGE('',*,*,#790,.F.);
#792=DIRECTION('',(0.,0.,-1.));
#793=VECTOR('',#792,1.);
#794=CARTESIAN_POINT('',(12.25,-15.,0.));
#795=LINE('',#794,#793);
#796=CARTESIAN_POINT('',(12.25,-15.,19.));
#797=VERTEX_POINT('',#796);
#798=EDGE_CURVE('E793',#797,#789,#795,.T.);
#799=ORIENTED_EDGE('',*,*,#798,.F.);
#800=DIRECTION('',(0.,-0.707106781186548,-0.707106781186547));
#801=VECTOR('',#800,1.);
#802=CARTESIAN_POINT('',(12.25,-11.,23.));
#803=LINE('',#802,#801);
#804=EDGE_CURVE('E468',#797,#253,#803,.F.);
#805=ORIENTED_EDGE('',*,*,#804,.T.);
#806=ORIENTED_EDGE('',*,*,#254,.F.);
#807=ORIENTED_EDGE('',*,*,#393,.F.);
#808=DIRECTION('',(0.,0.70710678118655,-0.707106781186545));
#809=VECTOR('',#808,1.);
#810=CARTESIAN_POINT('',(12.25,-8.9,16.5));
#811=LINE('',#810,#809);
#812=EDGE_CURVE('E413',#386,#213,#811,.T.);
#813=ORIENTED_EDGE('',*,*,#812,.T.);
#814=ORIENTED_EDGE('',*,*,#214,.F.);
#815=DIRECTION('',(0.,-0.707106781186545,-0.70710678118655));
#816=VECTOR('',#815,1.);
#817=CARTESIAN_POINT('',(12.25,7.90000000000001,15.5));
#818=LINE('',#817,#816);
#819=EDGE_CURVE('E409',#211,#347,#818,.F.);
#820=ORIENTED_EDGE('',*,*,#819,.T.);
#821=ORIENTED_EDGE('',*,*,#348,.T.);
#822=ORIENTED_EDGE('',*,*,#282,.F.);
#823=DIRECTION('',(0.,0.707106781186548,-0.707106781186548));
#824=VECTOR('',#823,1.);
#825=CARTESIAN_POINT('',(12.25,21.5,9.5));
#826=LINE('',#825,#824);
#827=EDGE_CURVE('E470',#277,#47,#826,.T.);
#828=ORIENTED_EDGE('',*,*,#827,.T.);
#829=ORIENTED_EDGE('',*,*,#48,.T.);
#830=DIRECTION('',(0.,0.894427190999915,-0.447213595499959));
#831=VECTOR('',#830,1.);
#832=CARTESIAN_POINT('',(12.25,14.,7.5));
#833=LINE('',#832,#831);
#834=CARTESIAN_POINT('',(12.25,14.,7.5));
#835=VERTEX_POINT('',#834);
#836=EDGE_CURVE('E11',#39,#835,#833,.T.);
#837=ORIENTED_EDGE('',*,*,#836,.T.);
#838=DIRECTION('',(0.,1.,0.));
#839=VECTOR('',#838,1.);
#840=CARTESIAN_POINT('',(12.25,14.,7.5));
#841=LINE('',#840,#839);
#842=CARTESIAN_POINT('',(12.25,12.,7.5));
#843=VERTEX_POINT('',#842);
#844=EDGE_CURVE('E56',#843,#835,#841,.T.);
#845=ORIENTED_EDGE('',*,*,#844,.F.);
#846=DIRECTION('',(0.,0.,-1.));
#847=VECTOR('',#846,1.);
#848=CARTESIAN_POINT('',(12.25,12.,0.));
#849=LINE('',#848,#847);
#850=CARTESIAN_POINT('',(12.25,12.,3.5));
#851=VERTEX_POINT('',#850);
#852=EDGE_CURVE('E1468',#843,#851,#849,.T.);
#853=ORIENTED_EDGE('',*,*,#852,.T.);
#854=DIRECTION('',(0.,-1.,0.));
#855=VECTOR('',#854,1.);
#856=CARTESIAN_POINT('',(12.25,14.,3.5));
#857=LINE('',#856,#855);
#858=CARTESIAN_POINT('',(12.25,14.,3.5));
#859=VERTEX_POINT('',#858);
#860=EDGE_CURVE('E404',#859,#851,#857,.T.);
#861=ORIENTED_EDGE('',*,*,#860,.F.);
#862=DIRECTION('',(0.,-0.894427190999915,-0.447213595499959));
#863=VECTOR('',#862,1.);
#864=CARTESIAN_POINT('',(12.25,14.,3.5));
#865=LINE('',#864,#863);
#866=EDGE_CURVE('E371',#859,#60,#865,.T.);
#867=ORIENTED_EDGE('',*,*,#866,.T.);
#868=ORIENTED_EDGE('',*,*,#63,.T.);
#869=DIRECTION('',(0.,-1.,0.));
#870=VECTOR('',#869,1.);
#871=CARTESIAN_POINT('',(12.25,16.,-4.33493649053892));
#872=LINE('',#871,#870);
#873=CARTESIAN_POINT('',(12.25,16.,-4.33493649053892));
#874=VERTEX_POINT('',#873);
#875=EDGE_CURVE('E1445',#874,#62,#872,.T.);
#876=ORIENTED_EDGE('',*,*,#875,.F.);
#877=DIRECTION('',(0.,0.,1.));
#878=VECTOR('',#877,1.);
#879=CARTESIAN_POINT('',(12.25,16.,0.));
#880=LINE('',#879,#878);
#881=CARTESIAN_POINT('',(12.25,16.,-8.66506350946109));
#882=VERTEX_POINT('',#881);
#883=EDGE_CURVE('E1443',#882,#874,#880,.T.);
#884=ORIENTED_EDGE('',*,*,#883,.F.);
#885=DIRECTION('',(0.,-1.,0.));
#886=VECTOR('',#885,1.);
#887=CARTESIAN_POINT('',(12.25,16.,-8.66506350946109));
#888=LINE('',#887,#886);
#889=EDGE_CURVE('E768',#882,#170,#888,.T.);
#890=ORIENTED_EDGE('',*,*,#889,.T.);
#891=EDGE_LOOP('',(#768,#774,#775,#783,#791,#799,#805,#806,#807,#813,#814,#820,#821,#822,#828,
#829,#837,#845,#853,#861,#867,#868,#876,#884,#890));
#892=FACE_BOUND('',#891,.T.);
#893=ADVANCED_FACE('F759',(#892),#767,.T.);
#894=CARTESIAN_POINT('',(15.25,12.,0.));
#895=DIRECTION('',(-1.,0.,0.));
#896=DIRECTION('',(0.,0.,1.));
#897=AXIS2_PLACEMENT_3D('',#894,#895,#896);
#898=PLANE('',#897);
#899=DIRECTION('',(0.,0.,-1.));
#900=VECTOR('',#899,1.);
#901=CARTESIAN_POINT('',(15.25,-15.,0.));
#902=LINE('',#901,#900);
#903=CARTESIAN_POINT('',(15.25,-15.,19.));
#904=VERTEX_POINT('',#903);
#905=CARTESIAN_POINT('',(15.25,-15.,-14.5));
#906=VERTEX_POINT('',#905);
#907=EDGE_CURVE('E795',#904,#906,#902,.T.);
#908=ORIENTED_EDGE('',*,*,#907,.T.);
#909=DIRECTION('',(0.,1.,0.));
#910=VECTOR('',#909,1.);
#911=CARTESIAN_POINT('',(15.25,12.,-14.5));
#912=LINE('',#911,#910);
#913=EDGE_CURVE('E474',#906,#158,#912,.T.);
#914=ORIENTED_EDGE('',*,*,#913,.T.);
#915=ORIENTED_EDGE('',*,*,#159,.F.);
#916=DIRECTION('',(0.,1.,0.));
#917=VECTOR('',#916,1.);
#918=CARTESIAN_POINT('',(15.25,6.,-9.99106001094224));
#919=LINE('',#918,#917);
#920=CARTESIAN_POINT('',(15.25,8.72707380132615,-9.99106001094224));
#921=VERTEX_POINT('',#920);
#922=EDGE_CURVE('E817',#921,#156,#919,.T.);
#923=ORIENTED_EDGE('',*,*,#922,.F.);
#924=CARTESIAN_POINT('',(15.25,8.72707380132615,-9.99106001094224));
#925=CARTESIAN_POINT('',(15.25,8.62392002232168,-9.86780864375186));
#926=CARTESIAN_POINT('',(15.25,8.52078014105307,-9.74454563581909));
#927=CARTESIAN_POINT('',(15.25,8.31453732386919,-9.49796935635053));
#928=CARTESIAN_POINT('',(15.25,8.21143439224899,-9.37465608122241));
#929=CARTESIAN_POINT('',(15.25,8.00510236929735,-9.12774610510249));
#930=CARTESIAN_POINT('',(15.25,7.9018733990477,-9.00414930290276));
#931=CARTESIAN_POINT('',(15.25,7.69552650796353,-8.75688214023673));
#932=CARTESIAN_POINT('',(15.25,7.59240857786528,-8.63321178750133));
#933=CARTESIAN_POINT('',(15.25,7.38087094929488,-8.37917141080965));
#934=CARTESIAN_POINT('',(15.25,7.27246015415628,-8.2487939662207));
#935=CARTESIAN_POINT('',(15.25,7.11009050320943,-8.05299132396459));
#936=CARTESIAN_POINT('',(15.25,7.05600055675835,-7.98767488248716));
#937=CARTESIAN_POINT('',(15.25,6.94795351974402,-7.85693611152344));
#938=CARTESIAN_POINT('',(15.25,6.89399642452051,-7.79151378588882));
#939=CARTESIAN_POINT('',(15.25,6.78635205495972,-7.66059005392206));
#940=CARTESIAN_POINT('',(15.25,6.7326645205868,-7.59508886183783));
#941=CARTESIAN_POINT('',(15.25,6.62561682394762,-7.46380527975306));
#942=CARTESIAN_POINT('',(15.25,6.57225670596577,-7.39802285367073));
#943=CARTESIAN_POINT('',(15.25,6.46615601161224,-7.26601372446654));
#944=CARTESIAN_POINT('',(15.25,6.41341512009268,-7.1997872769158));
#945=CARTESIAN_POINT('',(15.25,6.33529954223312,-7.09968061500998));
#946=CARTESIAN_POINT('',(15.25,6.30942971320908,-7.06618755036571));
#947=CARTESIAN_POINT('',(15.25,6.25823113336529,-6.99879138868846));
#948=CARTESIAN_POINT('',(15.25,6.2329023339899,-6.96488832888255));
#949=CARTESIAN_POINT('',(15.25,6.19506261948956,-6.91273846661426));
#950=CARTESIAN_POINT('',(15.25,6.18220496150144,-6.89474395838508));
#951=CARTESIAN_POINT('',(15.25,6.15685880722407,-6.85849006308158));
#952=CARTESIAN_POINT('',(15.25,6.1443703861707,-6.84023062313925));
#953=CARTESIAN_POINT('',(15.25,6.11989409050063,-6.80329418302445));
#954=CARTESIAN_POINT('',(15.25,6.10790790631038,-6.78461605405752));
#955=CARTESIAN_POINT('',(15.25,6.08477030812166,-6.74675253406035));
#956=CARTESIAN_POINT('',(15.25,6.07361856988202,-6.72756734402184));
#957=CARTESIAN_POINT('',(15.25,6.05119713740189,-6.6858104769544));
#958=CARTESIAN_POINT('',(15.25,6.04011886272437,-6.66313384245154));
#959=CARTESIAN_POINT('',(15.25,6.02109333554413,-6.61663690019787));
#960=CARTESIAN_POINT('',(15.25,6.01311750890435,-6.59282941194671));
#961=CARTESIAN_POINT('',(15.25,6.00524561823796,-6.55726748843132));
#962=CARTESIAN_POINT('',(15.25,6.00331329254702,-6.54597308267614));
#963=CARTESIAN_POINT('',(15.25,6.00067414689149,-6.52312615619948));
#964=CARTESIAN_POINT('',(15.25,5.99998021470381,-6.51157217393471));
#965=CARTESIAN_POINT('',(15.25,5.99999999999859,-6.50000000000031));
#966=B_SPLINE_CURVE_WITH_KNOTS('',3,(#924,#925,#926,#927,#928,#929,#930,#931,#932,#933,#934,
#935,#936,#937,#938,#939,#940,#941,#942,#943,#944,#945,#946,#947,#948,#949,#950,#951,#952,#953,
#954,#955,#956,#957,#958,#959,#960,#961,#962,#963,#964,#965),.UNSPECIFIED.,.F.,.F.,(4,2,2,2,2,2,
2,2,2,2,2,2,2,2,2,2,2,2,2,2,4),(0.,0.482166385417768,0.964377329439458,1.44748339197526,
1.93054542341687,2.4392302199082,2.69364635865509,2.94805344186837,3.20212889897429,
3.45623799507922,3.71021160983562,3.83717102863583,3.96411900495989,4.03046414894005,
4.09682271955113,4.16338914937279,4.22992957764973,4.3055468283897,4.38045013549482,
4.41476128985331,4.44942747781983),.UNSPECIFIED.);
#967=CARTESIAN_POINT('',(15.25,6.,-6.5));
#968=VERTEX_POINT('',#967);
#969=EDGE_CURVE('E745',#921,#968,#966,.T.);
#970=ORIENTED_EDGE('',*,*,#969,.T.);
#971=CARTESIAN_POINT('',(15.25,6.,-6.5));
#972=CARTESIAN_POINT('',(15.25,5.9999915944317,-6.49097094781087));
#973=CARTESIAN_POINT('',(15.25,6.00041027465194,-6.4819471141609));
#974=CARTESIAN_POINT('',(15.25,6.00203509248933,-6.46399019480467));
#975=CARTESIAN_POINT('',(15.25,6.00323945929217,-6.45505695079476));
#976=CARTESIAN_POINT('',(15.25,6.00633905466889,-6.43749285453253));
#977=CARTESIAN_POINT('',(15.25,6.00822039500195,-6.42885949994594));
#978=CARTESIAN_POINT('',(15.25,6.01258310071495,-6.41174377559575));
#979=CARTESIAN_POINT('',(15.25,6.01506474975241,-6.40326147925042));
#980=CARTESIAN_POINT('',(15.25,6.02495561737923,-6.37284346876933));
#981=CARTESIAN_POINT('',(15.25,6.03383174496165,-6.3513872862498));
#982=CARTESIAN_POINT('',(15.25,6.05359866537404,-6.30941924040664));
#983=CARTESIAN_POINT('',(15.25,6.0644946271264,-6.28890997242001));
#984=CARTESIAN_POINT('',(15.25,6.08771923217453,-6.2481559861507));
#985=CARTESIAN_POINT('',(15.25,6.10007310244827,-6.2279258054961));
#986=CARTESIAN_POINT('',(15.25,6.125532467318,-6.18798917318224));
#987=CARTESIAN_POINT('',(15.25,6.13863695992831,-6.16828207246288));
#988=CARTESIAN_POINT('',(15.25,6.16737136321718,-6.12624946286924));
#989=CARTESIAN_POINT('',(15.25,6.18308290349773,-6.10398003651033));
#990=CARTESIAN_POINT('',(15.25,6.21493831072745,-6.05975164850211));
#991=CARTESIAN_POINT('',(15.25,6.23108221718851,-6.03779271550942));
#992=CARTESIAN_POINT('',(15.25,6.2799566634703,-5.97222771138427));
#993=CARTESIAN_POINT('',(15.25,6.3131210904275,-5.92894597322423));
#994=CARTESIAN_POINT('',(15.25,6.38008386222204,-5.84279533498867));
#995=CARTESIAN_POINT('',(15.25,6.41388293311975,-5.79992700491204));
#996=CARTESIAN_POINT('',(15.25,6.4818345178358,-5.7144834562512));
#997=CARTESIAN_POINT('',(15.25,6.5159869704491,-5.67190818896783));
#998=CARTESIAN_POINT('',(15.25,6.61784330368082,-5.54560709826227));
#999=CARTESIAN_POINT('',(15.25,6.6858669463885,-5.46213972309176));
#1000=CARTESIAN_POINT('',(15.25,6.822281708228,-5.29558947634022));
#1001=CARTESIAN_POINT('',(15.25,6.8906725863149,-5.21250640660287));
#1002=CARTESIAN_POINT('',(15.25,7.10411651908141,-4.95391773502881));
#1003=CARTESIAN_POINT('',(15.25,7.24955710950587,-4.77873219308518));
#1004=CARTESIAN_POINT('',(15.25,7.54083834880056,-4.42862053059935));
#1005=CARTESIAN_POINT('',(15.25,7.68667908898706,-4.25369448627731));
#1006=CARTESIAN_POINT('',(15.25,7.98156720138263,-3.900386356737));
#1007=CARTESIAN_POINT('',(15.25,8.13061853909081,-3.72200757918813));
#1008=CARTESIAN_POINT('',(15.25,8.42879865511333,-3.36539423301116));
#1009=CARTESIAN_POINT('',(15.25,8.57792740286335,-3.18715963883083));
#1010=CARTESIAN_POINT('',(15.25,8.72707380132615,-3.00893998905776));
#1011=B_SPLINE_CURVE_WITH_KNOTS('',3,(#971,#972,#973,#974,#975,#976,#977,#978,#979,#980,#981,
#982,#983,#984,#985,#986,#987,#988,#989,#990,#991,#992,#993,#994,#995,#996,#997,#998,#999,#1000,
#1001,#1002,#1003,#1004,#1005,#1006,#1007,#1008,#1009,#1010),.UNSPECIFIED.,.F.,.F.,(4,2,2,2,2,2,
2,2,2,2,2,2,2,2,2,2,2,2,2,4),(0.,0.0270691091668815,0.0540774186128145,0.0805605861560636,
0.107056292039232,0.176499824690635,0.246123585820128,0.317205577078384,0.388194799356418,
0.469948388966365,0.551709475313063,0.715277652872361,0.87904598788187,1.04278641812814,
1.36580975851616,1.68864211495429,2.37171129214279,3.05495205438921,3.75231668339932,
4.44949840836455),.UNSPECIFIED.);
#1012=CARTESIAN_POINT('',(15.25,8.72707380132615,-3.00893998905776));
#1013=VERTEX_POINT('',#1012);
#1014=EDGE_CURVE('E750',#968,#1013,#1011,.T.);
#1015=ORIENTED_EDGE('',*,*,#1014,.T.);
#1016=DIRECTION('',(0.,1.,0.));
#1017=VECTOR('',#1016,1.);
#1018=CARTESIAN_POINT('',(15.25,6.,-3.00893998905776));
#1019=LINE('',#1018,#1017);
#1020=EDGE_CURVE('E818',#1013,#74,#1019,.T.);
#1021=ORIENTED_EDGE('',*,*,#1020,.T.);
#1022=ORIENTED_EDGE('',*,*,#75,.F.);
#1023=DIRECTION('',(0.,0.894427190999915,0.447213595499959));
#1024=VECTOR('',#1023,1.);
#1025=CARTESIAN_POINT('',(15.25,11.,2.));
#1026=LINE('',#1025,#1024);
#1027=CARTESIAN_POINT('',(15.25,14.,3.5));
#1028=VERTEX_POINT('',#1027);
#1029=EDGE_CURVE('E365',#70,#1028,#1026,.T.);
#1030=ORIENTED_EDGE('',*,*,#1029,.T.);
#1031=DIRECTION('',(0.,0.,-1.));
#1032=VECTOR('',#1031,1.);
#1033=CARTESIAN_POINT('',(15.25,14.,3.5));
#1034=LINE('',#1033,#1032);
#1035=CARTESIAN_POINT('',(15.25,14.,7.5));
#1036=VERTEX_POINT('',#1035);
#1037=EDGE_CURVE('E345',#1036,#1028,#1034,.T.);
#1038=ORIENTED_EDGE('',*,*,#1037,.F.);
#1039=DIRECTION('',(0.,-0.894427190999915,0.447213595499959));
#1040=VECTOR('',#1039,1.);
#1041=CARTESIAN_POINT('',(15.25,15.4,6.79999999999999));
#1042=LINE('',#1041,#1040);
#1043=EDGE_CURVE('E50',#1036,#31,#1042,.T.);
#1044=ORIENTED_EDGE('',*,*,#1043,.T.);
#1045=ORIENTED_EDGE('',*,*,#32,.F.);
#1046=DIRECTION('',(0.,-1.,0.));
#1047=VECTOR('',#1046,1.);
#1048=CARTESIAN_POINT('',(15.25,12.,19.));
#1049=LINE('',#1048,#1047);
#1050=EDGE_CURVE('E476',#29,#904,#1049,.T.);
#1051=ORIENTED_EDGE('',*,*,#1050,.T.);
#1052=EDGE_LOOP('',(#908,#914,#915,#923,#970,#1015,#1021,#1022,#1030,#1038,#1044,#1045,#1051));
#1053=FACE_BOUND('',#1052,.T.);
#1054=ADVANCED_FACE('F360',(#1053),#898,.F.);
#1055=CARTESIAN_POINT('',(-15.,6.,-6.5));
#1056=DIRECTION('',(0.,1.,0.));
#1057=DIRECTION('',(0.,0.,1.));
#1058=AXIS2_PLACEMENT_3D('',#1055,#1056,#1057);
#1059=CYLINDRICAL_SURFACE('',#1058,3.5);
#1060=ORIENTED_EDGE('',*,*,#758,.F.);
#1061=CARTESIAN_POINT('',(-15.,8.72707380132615,-6.5));
#1062=DIRECTION('',(0.,1.,0.));
#1063=DIRECTION('',(0.,0.,1.));
#1064=AXIS2_PLACEMENT_3D('',#1061,#1062,#1063);
#1065=CIRCLE('',#1064,3.5);
#1066=EDGE_CURVE('E742',#751,#659,#1065,.T.);
#1067=ORIENTED_EDGE('',*,*,#1066,.T.);
#1068=ORIENTED_EDGE('',*,*,#660,.T.);
#1069=ORIENTED_EDGE('',*,*,#150,.T.);
#1070=ORIENTED_EDGE('',*,*,#441,.F.);
#1071=CARTESIAN_POINT('',(-15.,16.,-6.5));
#1072=DIRECTION('',(0.,1.,0.));
#1073=DIRECTION('',(0.,0.,1.));
#1074=AXIS2_PLACEMENT_3D('',#1071,#1072,#1073);
#1075=CIRCLE('',#1074,3.5);
#1076=EDGE_CURVE('E840',#426,#434,#1075,.T.);
#1077=ORIENTED_EDGE('',*,*,#1076,.F.);
#1078=ORIENTED_EDGE('',*,*,#427,.T.);
#1079=ORIENTED_EDGE('',*,*,#196,.T.);
#1080=EDGE_LOOP('',(#1060,#1067,#1068,#1069,#1070,#1077,#1078,#1079));
#1081=FACE_BOUND('',#1080,.T.);
#1082=ADVANCED_FACE('F758',(#1081),#1059,.T.);
#1083=CARTESIAN_POINT('',(15.,6.,-6.5));
#1084=DIRECTION('',(0.,1.,0.));
#1085=DIRECTION('',(0.,0.,1.));
#1086=AXIS2_PLACEMENT_3D('',#1083,#1084,#1085);
#1087=CYLINDRICAL_SURFACE('',#1086,3.5);
#1088=ORIENTED_EDGE('',*,*,#1020,.F.);
#1089=CARTESIAN_POINT('',(15.,8.72707380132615,-6.5));
#1090=DIRECTION('',(0.,1.,0.));
#1091=DIRECTION('',(0.,0.,1.));
#1092=AXIS2_PLACEMENT_3D('',#1089,#1090,#1091);
#1093=CIRCLE('',#1092,3.5);
#1094=EDGE_CURVE('E739',#1013,#921,#1093,.T.);
#1095=ORIENTED_EDGE('',*,*,#1094,.T.);
#1096=ORIENTED_EDGE('',*,*,#922,.T.);
#1097=ORIENTED_EDGE('',*,*,#173,.T.);
#1098=ORIENTED_EDGE('',*,*,#889,.F.);
#1099=CARTESIAN_POINT('',(15.,16.,-6.5));
#1100=DIRECTION('',(0.,1.,0.));
#1101=DIRECTION('',(0.,0.,1.));
#1102=AXIS2_PLACEMENT_3D('',#1099,#1100,#1101);
#1103=CIRCLE('',#1102,3.5);
#1104=EDGE_CURVE('E1438',#874,#882,#1103,.T.);
#1105=ORIENTED_EDGE('',*,*,#1104,.F.);
#1106=ORIENTED_EDGE('',*,*,#875,.T.);
#1107=ORIENTED_EDGE('',*,*,#82,.T.);
#1108=EDGE_LOOP('',(#1088,#1095,#1096,#1097,#1098,#1105,#1106,#1107));
#1109=FACE_BOUND('',#1108,.T.);
#1110=ADVANCED_FACE('F1250',(#1109),#1087,.T.);
#1111=CARTESIAN_POINT('',(0.,-15.,15.5));
#1112=DIRECTION('',(0.,0.,1.));
#1113=DIRECTION('',(1.,0.,0.));
#1114=AXIS2_PLACEMENT_3D('',#1111,#1112,#1113);
#1115=PLANE('',#1114);
#1116=DIRECTION('',(1.,0.,0.));
#1117=VECTOR('',#1116,1.);
#1118=CARTESIAN_POINT('',(0.,-12.,15.5));
#1119=LINE('',#1118,#1117);
#1120=EDGE_CURVE('E809',#527,#781,#1119,.T.);
#1121=ORIENTED_EDGE('',*,*,#1120,.F.);
#1122=ORIENTED_EDGE('',*,*,#528,.F.);
#1123=DIRECTION('',(1.,0.,0.));
#1124=VECTOR('',#1123,1.);
#1125=CARTESIAN_POINT('',(0.,-15.,15.5));
#1126=LINE('',#1125,#1124);
#1127=EDGE_CURVE('E800',#519,#789,#1126,.T.);
#1128=ORIENTED_EDGE('',*,*,#1127,.T.);
#1129=ORIENTED_EDGE('',*,*,#790,.T.);
#1130=EDGE_LOOP('',(#1121,#1122,#1128,#1129));
#1131=FACE_BOUND('',#1130,.T.);
#1132=ADVANCED_FACE('F931',(#1131),#1115,.T.);
#1133=CARTESIAN_POINT('',(0.,-15.,0.));
#1134=DIRECTION('',(0.,1.,0.));
#1135=DIRECTION('',(0.,0.,1.));
#1136=AXIS2_PLACEMENT_3D('',#1133,#1134,#1135);
#1137=PLANE('',#1136);
#1138=ORIENTED_EDGE('',*,*,#622,.F.);
#1139=DIRECTION('',(1.,0.,0.));
#1140=VECTOR('',#1139,1.);
#1141=CARTESIAN_POINT('',(0.,-15.,-14.5));
#1142=LINE('',#1141,#1140);
#1143=EDGE_CURVE('E478',#613,#906,#1142,.T.);
#1144=ORIENTED_EDGE('',*,*,#1143,.T.);
#1145=ORIENTED_EDGE('',*,*,#907,.F.);
#1146=DIRECTION('',(-1.,0.,0.));
#1147=VECTOR('',#1146,1.);
#1148=CARTESIAN_POINT('',(0.,-15.,19.));
#1149=LINE('',#1148,#1147);
#1150=EDGE_CURVE('E480',#904,#797,#1149,.T.);
#1151=ORIENTED_EDGE('',*,*,#1150,.T.);
#1152=ORIENTED_EDGE('',*,*,#798,.T.);
#1153=ORIENTED_EDGE('',*,*,#1127,.F.);
#1154=ORIENTED_EDGE('',*,*,#520,.T.);
#1155=DIRECTION('',(-1.,0.,0.));
#1156=VECTOR('',#1155,1.);
#1157=CARTESIAN_POINT('',(0.,-15.,19.));
#1158=LINE('',#1157,#1156);
#1159=EDGE_CURVE('E482',#511,#621,#1158,.T.);
#1160=ORIENTED_EDGE('',*,*,#1159,.T.);
#1161=EDGE_LOOP('',(#1138,#1144,#1145,#1151,#1152,#1153,#1154,#1160));
#1162=FACE_BOUND('',#1161,.T.);
#1163=ADVANCED_FACE('F791',(#1162),#1137,.F.);
#1164=CARTESIAN_POINT('',(0.,-12.,0.));
#1165=DIRECTION('',(0.,1.,0.));
#1166=DIRECTION('',(0.,0.,1.));
#1167=AXIS2_PLACEMENT_3D('',#1164,#1165,#1166);
#1168=PLANE('',#1167);
#1169=ORIENTED_EDGE('',*,*,#567,.F.);
#1170=ORIENTED_EDGE('',*,*,#534,.T.);
#1171=ORIENTED_EDGE('',*,*,#1120,.T.);
#1172=ORIENTED_EDGE('',*,*,#782,.T.);
#1173=EDGE_LOOP('',(#1169,#1170,#1171,#1172));
#1174=FACE_BOUND('',#1173,.T.);
#1175=ADVANCED_FACE('F930',(#1174),#1168,.T.);
#1176=CARTESIAN_POINT('',(-15.,16.,-6.5));
#1177=DIRECTION('',(0.,1.,0.));
#1178=DIRECTION('',(0.,0.,1.));
#1179=AXIS2_PLACEMENT_3D('',#1176,#1177,#1178);
#1180=PLANE('',#1179);
#1181=CARTESIAN_POINT('',(-15.,16.,-6.5));
#1182=DIRECTION('',(0.,1.,0.));
#1183=DIRECTION('',(0.,0.,1.));
#1184=AXIS2_PLACEMENT_3D('',#1181,#1182,#1183);
#1185=CIRCLE('',#1184,0.999999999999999);
#1186=CARTESIAN_POINT('',(-15.,16.,-5.5));
#1187=VERTEX_POINT('',#1186);
#1188=EDGE_CURVE('E842',#1187,#1187,#1185,.T.);
#1189=ORIENTED_EDGE('',*,*,#1188,.F.);
#1190=EDGE_LOOP('',(#1189));
#1191=FACE_BOUND('',#1190,.T.);
#1192=ORIENTED_EDGE('',*,*,#1076,.T.);
#1193=ORIENTED_EDGE('',*,*,#435,.F.);
#1194=EDGE_LOOP('',(#1192,#1193));
#1195=FACE_BOUND('',#1194,.T.);
#1196=ADVANCED_FACE('F1213',(#1191,#1195),#1180,.T.);
#1197=CARTESIAN_POINT('',(-15.,8.,-6.5));
#1198=DIRECTION('',(0.,1.,0.));
#1199=DIRECTION('',(0.,0.,1.));
#1200=AXIS2_PLACEMENT_3D('',#1197,#1198,#1199);
#1201=CONICAL_SURFACE('',#1200,0.999999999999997,1.02974425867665);
#1202=CARTESIAN_POINT('',(-15.,7.39913938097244,-6.5));
#1203=VERTEX_POINT('',#1202);
#1204=VERTEX_LOOP('',#1203);
#1205=FACE_BOUND('',#1204,.T.);
#1206=CARTESIAN_POINT('',(-15.,8.,-6.5));
#1207=DIRECTION('',(0.,1.,0.));
#1208=DIRECTION('',(0.,0.,1.));
#1209=AXIS2_PLACEMENT_3D('',#1206,#1207,#1208);
#1210=CIRCLE('',#1209,0.999999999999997);
#1211=CARTESIAN_POINT('',(-15.,8.,-5.50000000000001));
#1212=VERTEX_POINT('',#1211);
#1213=EDGE_CURVE('E837',#1212,#1212,#1210,.T.);
#1214=ORIENTED_EDGE('',*,*,#1213,.T.);
#1215=EDGE_LOOP('',(#1214));
#1216=FACE_BOUND('',#1215,.T.);
#1217=ADVANCED_FACE('F1203',(#1205,#1216),#1201,.F.);
#1218=CARTESIAN_POINT('',(-15.,16.,-6.5));
#1219=DIRECTION('',(0.,1.,0.));
#1220=DIRECTION('',(0.,0.,1.));
#1221=AXIS2_PLACEMENT_3D('',#1218,#1219,#1220);
#1222=CYLINDRICAL_SURFACE('',#1221,0.999999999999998);
#1223=ORIENTED_EDGE('',*,*,#1213,.F.);
#1224=EDGE_LOOP('',(#1223));
#1225=FACE_BOUND('',#1224,.T.);
#1226=ORIENTED_EDGE('',*,*,#1188,.T.);
#1227=EDGE_LOOP('',(#1226));
#1228=FACE_BOUND('',#1227,.T.);
#1229=ADVANCED_FACE('F1184',(#1225,#1228),#1222,.F.);
#1230=CARTESIAN_POINT('',(15.,16.,-6.5));
#1231=DIRECTION('',(0.,1.,0.));
#1232=DIRECTION('',(0.,0.,1.));
#1233=AXIS2_PLACEMENT_3D('',#1230,#1231,#1232);
#1234=PLANE('',#1233);
#1235=CARTESIAN_POINT('',(15.,16.,-6.5));
#1236=DIRECTION('',(0.,1.,0.));
#1237=DIRECTION('',(0.,0.,1.));
#1238=AXIS2_PLACEMENT_3D('',#1235,#1236,#1237);
#1239=CIRCLE('',#1238,0.999999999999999);
#1240=CARTESIAN_POINT('',(15.,16.,-5.5));
#1241=VERTEX_POINT('',#1240);
#1242=EDGE_CURVE('E441',#1241,#1241,#1239,.T.);
#1243=ORIENTED_EDGE('',*,*,#1242,.F.);
#1244=EDGE_LOOP('',(#1243));
#1245=FACE_BOUND('',#1244,.T.);
#1246=ORIENTED_EDGE('',*,*,#1104,.T.);
#1247=ORIENTED_EDGE('',*,*,#883,.T.);
#1248=EDGE_LOOP('',(#1246,#1247));
#1249=FACE_BOUND('',#1248,.T.);
#1250=ADVANCED_FACE('F1174',(#1245,#1249),#1234,.T.);
#1251=CARTESIAN_POINT('',(15.,8.,-6.5));
#1252=DIRECTION('',(0.,1.,0.));
#1253=DIRECTION('',(0.,0.,1.));
#1254=AXIS2_PLACEMENT_3D('',#1251,#1252,#1253);
#1255=CONICAL_SURFACE('',#1254,0.999999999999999,1.02974425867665);
#1256=CARTESIAN_POINT('',(15.,7.39913938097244,-6.5));
#1257=VERTEX_POINT('',#1256);
#1258=VERTEX_LOOP('',#1257);
#1259=FACE_BOUND('',#1258,.T.);
#1260=CARTESIAN_POINT('',(15.,8.,-6.5));
#1261=DIRECTION('',(0.,1.,0.));
#1262=DIRECTION('',(0.,0.,1.));
#1263=AXIS2_PLACEMENT_3D('',#1260,#1261,#1262);
#1264=CIRCLE('',#1263,0.999999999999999);
#1265=CARTESIAN_POINT('',(15.,8.,-5.5));
#1266=VERTEX_POINT('',#1265);
#1267=EDGE_CURVE('E1436',#1266,#1266,#1264,.T.);
#1268=ORIENTED_EDGE('',*,*,#1267,.T.);
#1269=EDGE_LOOP('',(#1268));
#1270=FACE_BOUND('',#1269,.T.);
#1271=ADVANCED_FACE('F1164',(#1259,#1270),#1255,.F.);
#1272=CARTESIAN_POINT('',(15.,16.,-6.5));
#1273=DIRECTION('',(0.,1.,0.));
#1274=DIRECTION('',(0.,0.,1.));
#1275=AXIS2_PLACEMENT_3D('',#1272,#1273,#1274);
#1276=CYLINDRICAL_SURFACE('',#1275,0.999999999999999);
#1277=ORIENTED_EDGE('',*,*,#1267,.F.);
#1278=EDGE_LOOP('',(#1277));
#1279=FACE_BOUND('',#1278,.T.);
#1280=ORIENTED_EDGE('',*,*,#1242,.T.);
#1281=EDGE_LOOP('',(#1280));
#1282=FACE_BOUND('',#1281,.T.);
#1283=ADVANCED_FACE('F1155',(#1279,#1282),#1276,.F.);
#1284=CARTESIAN_POINT('',(15.,8.72707380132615,-6.5));
#1285=DIRECTION('',(0.,1.,0.));
#1286=DIRECTION('',(0.,0.,1.));
#1287=AXIS2_PLACEMENT_3D('',#1284,#1285,#1286);
#1288=CONICAL_SURFACE('',#1287,3.5,0.872664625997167);
#1289=ORIENTED_EDGE('',*,*,#1094,.F.);
#1290=ORIENTED_EDGE('',*,*,#1014,.F.);
#1291=ORIENTED_EDGE('',*,*,#969,.F.);
#1292=EDGE_LOOP('',(#1289,#1290,#1291));
#1293=FACE_BOUND('',#1292,.T.);
#1294=ADVANCED_FACE('F535',(#1293),#1288,.T.);
#1295=CARTESIAN_POINT('',(-15.,8.72707380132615,-6.5));
#1296=DIRECTION('',(0.,1.,0.));
#1297=DIRECTION('',(0.,0.,1.));
#1298=AXIS2_PLACEMENT_3D('',#1295,#1296,#1297);
#1299=CONICAL_SURFACE('',#1298,3.5,0.872664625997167);
#1300=ORIENTED_EDGE('',*,*,#1066,.F.);
#1301=ORIENTED_EDGE('',*,*,#752,.F.);
#1302=ORIENTED_EDGE('',*,*,#707,.F.);
#1303=EDGE_LOOP('',(#1300,#1301,#1302));
#1304=FACE_BOUND('',#1303,.T.);
#1305=ADVANCED_FACE('F525',(#1304),#1299,.T.);
#1306=CARTESIAN_POINT('',(0.,12.,-14.5));
#1307=DIRECTION('',(0.,0.707106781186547,-0.707106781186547));
#1308=DIRECTION('',(1.,0.,0.));
#1309=AXIS2_PLACEMENT_3D('',#1306,#1307,#1308);
#1310=PLANE('',#1309);
#1311=ORIENTED_EDGE('',*,*,#773,.F.);
#1312=ORIENTED_EDGE('',*,*,#167,.F.);
#1313=DIRECTION('',(0.577350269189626,0.577350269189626,0.577350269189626));
#1314=VECTOR('',#1313,1.);
#1315=CARTESIAN_POINT('',(10.1666666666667,6.91666666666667,-19.5833333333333));
#1316=LINE('',#1315,#1314);
#1317=EDGE_CURVE('E438',#582,#158,#1316,.T.);
#1318=ORIENTED_EDGE('',*,*,#1317,.F.);
#1319=ORIENTED_EDGE('',*,*,#583,.F.);
#1320=EDGE_LOOP('',(#1311,#1312,#1318,#1319));
#1321=FACE_BOUND('',#1320,.T.);
#1322=ADVANCED_FACE('F534',(#1321),#1310,.T.);
#1323=CARTESIAN_POINT('',(14.25,12.,-15.5));
#1324=DIRECTION('',(-0.707106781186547,0.,0.707106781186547));
#1325=DIRECTION('',(0.,-1.,0.));
#1326=AXIS2_PLACEMENT_3D('',#1323,#1324,#1325);
#1327=PLANE('',#1326);
#1328=ORIENTED_EDGE('',*,*,#1317,.T.);
#1329=ORIENTED_EDGE('',*,*,#913,.F.);
#1330=DIRECTION('',(-0.577350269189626,0.577350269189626,-0.577350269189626));
#1331=VECTOR('',#1330,1.);
#1332=CARTESIAN_POINT('',(5.58333333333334,-5.33333333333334,-24.1666666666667));
#1333=LINE('',#1332,#1331);
#1334=EDGE_CURVE('E442',#590,#906,#1333,.F.);
#1335=ORIENTED_EDGE('',*,*,#1334,.F.);
#1336=ORIENTED_EDGE('',*,*,#591,.F.);
#1337=EDGE_LOOP('',(#1328,#1329,#1335,#1336));
#1338=FACE_BOUND('',#1337,.T.);
#1339=ADVANCED_FACE('F563',(#1338),#1327,.F.);
#1340=CARTESIAN_POINT('',(0.,-15.,-14.5));
#1341=DIRECTION('',(0.,0.707106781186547,0.707106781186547));
#1342=DIRECTION('',(1.,0.,0.));
#1343=AXIS2_PLACEMENT_3D('',#1340,#1341,#1342);
#1344=PLANE('',#1343);
#1345=ORIENTED_EDGE('',*,*,#1334,.T.);
#1346=ORIENTED_EDGE('',*,*,#1143,.F.);
#1347=DIRECTION('',(0.577350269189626,0.577350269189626,-0.577350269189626));
#1348=VECTOR('',#1347,1.);
#1349=CARTESIAN_POINT('',(-10.1666666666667,-9.91666666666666,-19.5833333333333));
#1350=LINE('',#1349,#1348);
#1351=EDGE_CURVE('E445',#549,#613,#1350,.F.);
#1352=ORIENTED_EDGE('',*,*,#1351,.F.);
#1353=ORIENTED_EDGE('',*,*,#597,.F.);
#1354=EDGE_LOOP('',(#1345,#1346,#1352,#1353));
#1355=FACE_BOUND('',#1354,.T.);
#1356=ADVANCED_FACE('F556',(#1355),#1344,.F.);
#1357=CARTESIAN_POINT('',(-15.25,12.,-14.5));
#1358=DIRECTION('',(0.707106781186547,0.,0.707106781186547));
#1359=DIRECTION('',(0.,-1.,0.));
#1360=AXIS2_PLACEMENT_3D('',#1357,#1358,#1359);
#1361=PLANE('',#1360);
#1362=ORIENTED_EDGE('',*,*,#1351,.T.);
#1363=ORIENTED_EDGE('',*,*,#614,.F.);
#1364=DIRECTION('',(-0.577350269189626,0.577350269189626,0.577350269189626));
#1365=VECTOR('',#1364,1.);
#1366=CARTESIAN_POINT('',(-15.25,12.,-14.5));
#1367=LINE('',#1366,#1365);
#1368=EDGE_CURVE('E436',#551,#189,#1367,.T.);
#1369=ORIENTED_EDGE('',*,*,#1368,.F.);
#1370=ORIENTED_EDGE('',*,*,#552,.F.);
#1371=EDGE_LOOP('',(#1362,#1363,#1369,#1370));
#1372=FACE_BOUND('',#1371,.T.);
#1373=ADVANCED_FACE('F549',(#1372),#1361,.F.);
#1374=CARTESIAN_POINT('',(0.,12.,-14.5));
#1375=DIRECTION('',(0.,0.707106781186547,-0.707106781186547));
#1376=DIRECTION('',(1.,0.,0.));
#1377=AXIS2_PLACEMENT_3D('',#1374,#1375,#1376);
#1378=PLANE('',#1377);
#1379=ORIENTED_EDGE('',*,*,#418,.F.);
#1380=ORIENTED_EDGE('',*,*,#558,.F.);
#1381=ORIENTED_EDGE('',*,*,#1368,.T.);
#1382=ORIENTED_EDGE('',*,*,#190,.F.);
#1383=EDGE_LOOP('',(#1379,#1380,#1381,#1382));
#1384=FACE_BOUND('',#1383,.T.);
#1385=ADVANCED_FACE('F540',(#1384),#1378,.T.);
#1386=CARTESIAN_POINT('',(0.,12.,19.));
#1387=DIRECTION('',(0.,0.707106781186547,0.707106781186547));
#1388=DIRECTION('',(-1.,0.,0.));
#1389=AXIS2_PLACEMENT_3D('',#1386,#1387,#1388);
#1390=PLANE('',#1389);
#1391=ORIENTED_EDGE('',*,*,#827,.F.);
#1392=ORIENTED_EDGE('',*,*,#278,.F.);
#1393=DIRECTION('',(-0.577350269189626,-0.577350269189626,0.577350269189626));
#1394=VECTOR('',#1393,1.);
#1395=CARTESIAN_POINT('',(10.1666666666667,6.91666666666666,24.0833333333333));
#1396=LINE('',#1395,#1394);
#1397=EDGE_CURVE('E433',#29,#269,#1396,.T.);
#1398=ORIENTED_EDGE('',*,*,#1397,.F.);
#1399=ORIENTED_EDGE('',*,*,#54,.F.);
#1400=EDGE_LOOP('',(#1391,#1392,#1398,#1399));
#1401=FACE_BOUND('',#1400,.T.);
#1402=ADVANCED_FACE('F548',(#1401),#1390,.T.);
#1403=CARTESIAN_POINT('',(15.25,12.,19.));
#1404=DIRECTION('',(-0.707106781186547,0.,-0.707106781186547));
#1405=DIRECTION('',(0.,-1.,0.));
#1406=AXIS2_PLACEMENT_3D('',#1403,#1404,#1405);
#1407=PLANE('',#1406);
#1408=ORIENTED_EDGE('',*,*,#1397,.T.);
#1409=ORIENTED_EDGE('',*,*,#270,.F.);
#1410=DIRECTION('',(0.577350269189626,-0.577350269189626,-0.577350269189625));
#1411=VECTOR('',#1410,1.);
#1412=CARTESIAN_POINT('',(6.25,-5.99999999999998,28.));
#1413=LINE('',#1412,#1411);
#1414=EDGE_CURVE('E428',#904,#261,#1413,.F.);
#1415=ORIENTED_EDGE('',*,*,#1414,.F.);
#1416=ORIENTED_EDGE('',*,*,#1050,.F.);
#1417=EDGE_LOOP('',(#1408,#1409,#1415,#1416));
#1418=FACE_BOUND('',#1417,.T.);
#1419=ADVANCED_FACE('F584',(#1418),#1407,.F.);
#1420=CARTESIAN_POINT('',(0.,-14.,20.));
#1421=DIRECTION('',(0.,0.707106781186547,-0.707106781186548));
#1422=DIRECTION('',(1.,0.,0.));
#1423=AXIS2_PLACEMENT_3D('',#1420,#1421,#1422);
#1424=PLANE('',#1423);
#1425=ORIENTED_EDGE('',*,*,#804,.F.);
#1426=ORIENTED_EDGE('',*,*,#1150,.F.);
#1427=ORIENTED_EDGE('',*,*,#1414,.T.);
#1428=ORIENTED_EDGE('',*,*,#262,.F.);
#1429=EDGE_LOOP('',(#1425,#1426,#1427,#1428));
#1430=FACE_BOUND('',#1429,.T.);
#1431=ADVANCED_FACE('F576',(#1430),#1424,.F.);
#1432=CARTESIAN_POINT('',(0.,12.,19.));
#1433=DIRECTION('',(0.,0.707106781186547,0.707106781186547));
#1434=DIRECTION('',(-1.,0.,0.));
#1435=AXIS2_PLACEMENT_3D('',#1432,#1433,#1434);
#1436=PLANE('',#1435);
#1437=ORIENTED_EDGE('',*,*,#487,.F.);
#1438=ORIENTED_EDGE('',*,*,#122,.F.);
#1439=DIRECTION('',(-0.577350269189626,0.577350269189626,-0.577350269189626));
#1440=VECTOR('',#1439,1.);
#1441=CARTESIAN_POINT('',(-10.1666666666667,6.91666666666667,24.0833333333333));
#1442=LINE('',#1441,#1440);
#1443=EDGE_CURVE('E425',#305,#115,#1442,.T.);
#1444=ORIENTED_EDGE('',*,*,#1443,.F.);
#1445=ORIENTED_EDGE('',*,*,#306,.F.);
#1446=EDGE_LOOP('',(#1437,#1438,#1444,#1445));
#1447=FACE_BOUND('',#1446,.T.);
#1448=ADVANCED_FACE('F583',(#1447),#1436,.T.);
#1449=CARTESIAN_POINT('',(-14.25,8.9,20.));
#1450=DIRECTION('',(0.707106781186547,0.,-0.707106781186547));
#1451=DIRECTION('',(0.,-1.,0.));
#1452=AXIS2_PLACEMENT_3D('',#1449,#1450,#1451);
#1453=PLANE('',#1452);
#1454=ORIENTED_EDGE('',*,*,#1443,.T.);
#1455=ORIENTED_EDGE('',*,*,#628,.F.);
#1456=DIRECTION('',(0.577350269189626,0.577350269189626,0.577350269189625));
#1457=VECTOR('',#1456,1.);
#1458=CARTESIAN_POINT('',(-6.61666666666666,-6.36666666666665,27.6333333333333));
#1459=LINE('',#1458,#1457);
#1460=EDGE_CURVE('E429',#313,#621,#1459,.F.);
#1461=ORIENTED_EDGE('',*,*,#1460,.F.);
#1462=ORIENTED_EDGE('',*,*,#314,.F.);
#1463=EDGE_LOOP('',(#1454,#1455,#1461,#1462));
#1464=FACE_BOUND('',#1463,.T.);
#1465=ADVANCED_FACE('F605',(#1464),#1453,.F.);
#1466=CARTESIAN_POINT('',(0.,-14.,20.));
#1467=DIRECTION('',(0.,0.707106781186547,-0.707106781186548));
#1468=DIRECTION('',(1.,0.,0.));
#1469=AXIS2_PLACEMENT_3D('',#1466,#1467,#1468);
#1470=PLANE('',#1469);
#1471=ORIENTED_EDGE('',*,*,#1460,.T.);
#1472=ORIENTED_EDGE('',*,*,#1159,.F.);
#1473=ORIENTED_EDGE('',*,*,#512,.F.);
#1474=ORIENTED_EDGE('',*,*,#322,.F.);
#1475=EDGE_LOOP('',(#1471,#1472,#1473,#1474));
#1476=FACE_BOUND('',#1475,.T.);
#1477=ADVANCED_FACE('F597',(#1476),#1470,.F.);
#1478=CARTESIAN_POINT('',(0.,-8.9,16.5));
#1479=DIRECTION('',(0.,-0.707106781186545,-0.70710678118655));
#1480=DIRECTION('',(-1.,0.,0.));
#1481=AXIS2_PLACEMENT_3D('',#1478,#1479,#1480);
#1482=PLANE('',#1481);
#1483=ORIENTED_EDGE('',*,*,#502,.F.);
#1484=ORIENTED_EDGE('',*,*,#222,.F.);
#1485=ORIENTED_EDGE('',*,*,#812,.F.);
#1486=ORIENTED_EDGE('',*,*,#387,.F.);
#1487=EDGE_LOOP('',(#1483,#1484,#1485,#1486));
#1488=FACE_BOUND('',#1487,.T.);
#1489=ADVANCED_FACE('F604',(#1488),#1482,.T.);
#1490=CARTESIAN_POINT('',(0.,7.90000000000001,15.5));
#1491=DIRECTION('',(0.,-0.70710678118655,0.707106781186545));
#1492=DIRECTION('',(1.,0.,0.));
#1493=AXIS2_PLACEMENT_3D('',#1490,#1491,#1492);
#1494=PLANE('',#1493);
#1495=ORIENTED_EDGE('',*,*,#495,.F.);
#1496=ORIENTED_EDGE('',*,*,#356,.F.);
#1497=ORIENTED_EDGE('',*,*,#819,.F.);
#1498=ORIENTED_EDGE('',*,*,#236,.F.);
#1499=EDGE_LOOP('',(#1495,#1496,#1497,#1498));
#1500=FACE_BOUND('',#1499,.T.);
#1501=ADVANCED_FACE('F622',(#1500),#1494,.F.);
#1502=CARTESIAN_POINT('',(-15.25,14.,7.5));
#1503=DIRECTION('',(0.,0.,-1.));
#1504=DIRECTION('',(-1.,0.,0.));
#1505=AXIS2_PLACEMENT_3D('',#1502,#1503,#1504);
#1506=PLANE('',#1505);
#1507=DIRECTION('',(1.,0.,0.));
#1508=VECTOR('',#1507,1.);
#1509=CARTESIAN_POINT('',(-15.25,14.,7.5));
#1510=LINE('',#1509,#1508);
#1511=EDGE_CURVE('E346',#473,#835,#1510,.T.);
#1512=ORIENTED_EDGE('',*,*,#1511,.F.);
#1513=ORIENTED_EDGE('',*,*,#474,.T.);
#1514=DIRECTION('',(1.,0.,0.));
#1515=VECTOR('',#1514,1.);
#1516=CARTESIAN_POINT('',(-15.25,12.,7.5));
#1517=LINE('',#1516,#1515);
#1518=EDGE_CURVE('E1483',#465,#843,#1517,.T.);
#1519=ORIENTED_EDGE('',*,*,#1518,.T.);
#1520=ORIENTED_EDGE('',*,*,#844,.T.);
#1521=EDGE_LOOP('',(#1512,#1513,#1519,#1520));
#1522=FACE_BOUND('',#1521,.T.);
#1523=ADVANCED_FACE('F629',(#1522),#1506,.F.);
#1524=CARTESIAN_POINT('',(-15.25,14.,3.5));
#1525=DIRECTION('',(0.,0.,1.));
#1526=DIRECTION('',(1.,0.,0.));
#1527=AXIS2_PLACEMENT_3D('',#1524,#1525,#1526);
#1528=PLANE('',#1527);
#1529=DIRECTION('',(-1.,0.,0.));
#1530=VECTOR('',#1529,1.);
#1531=CARTESIAN_POINT('',(-15.25,14.,3.5));
#1532=LINE('',#1531,#1530);
#1533=EDGE_CURVE('E1464',#859,#449,#1532,.T.);
#1534=ORIENTED_EDGE('',*,*,#1533,.F.);
#1535=ORIENTED_EDGE('',*,*,#860,.T.);
#1536=DIRECTION('',(-1.,0.,0.));
#1537=VECTOR('',#1536,1.);
#1538=CARTESIAN_POINT('',(-15.25,12.,3.5));
#1539=LINE('',#1538,#1537);
#1540=EDGE_CURVE('E341',#851,#457,#1539,.T.);
#1541=ORIENTED_EDGE('',*,*,#1540,.T.);
#1542=ORIENTED_EDGE('',*,*,#458,.T.);
#1543=EDGE_LOOP('',(#1534,#1535,#1541,#1542));
#1544=FACE_BOUND('',#1543,.T.);
#1545=ADVANCED_FACE('F1030',(#1544),#1528,.F.);
#1546=CARTESIAN_POINT('',(0.,14.,0.));
#1547=DIRECTION('',(0.,1.,0.));
#1548=DIRECTION('',(0.,0.,1.));
#1549=AXIS2_PLACEMENT_3D('',#1546,#1547,#1548);
#1550=PLANE('',#1549);
#1551=ORIENTED_EDGE('',*,*,#645,.T.);
#1552=EDGE_CURVE('E336',#636,#473,#1510,.T.);
#1553=ORIENTED_EDGE('',*,*,#1552,.T.);
#1554=ORIENTED_EDGE('',*,*,#1511,.T.);
#1555=EDGE_CURVE('E340',#835,#1036,#1510,.T.);
#1556=ORIENTED_EDGE('',*,*,#1555,.T.);
#1557=ORIENTED_EDGE('',*,*,#1037,.T.);
#1558=EDGE_CURVE('E1466',#1028,#859,#1532,.T.);
#1559=ORIENTED_EDGE('',*,*,#1558,.T.);
#1560=ORIENTED_EDGE('',*,*,#1533,.T.);
#1561=EDGE_CURVE('E339',#449,#644,#1532,.T.);
#1562=ORIENTED_EDGE('',*,*,#1561,.T.);
#1563=EDGE_LOOP('',(#1551,#1553,#1554,#1556,#1557,#1559,#1560,#1562));
#1564=FACE_BOUND('',#1563,.T.);
#1565=ADVANCED_FACE('F334',(#1564),#1550,.T.);
#1566=CARTESIAN_POINT('',(0.,12.,0.));
#1567=DIRECTION('',(0.,1.,0.));
#1568=DIRECTION('',(0.,0.,1.));
#1569=AXIS2_PLACEMENT_3D('',#1566,#1567,#1568);
#1570=PLANE('',#1569);
#1571=ORIENTED_EDGE('',*,*,#466,.F.);
#1572=ORIENTED_EDGE('',*,*,#1540,.F.);
#1573=ORIENTED_EDGE('',*,*,#852,.F.);
#1574=ORIENTED_EDGE('',*,*,#1518,.F.);
#1575=EDGE_LOOP('',(#1571,#1572,#1573,#1574));
#1576=FACE_BOUND('',#1575,.T.);
#1577=ADVANCED_FACE('F638',(#1576),#1570,.F.);
#1578=CARTESIAN_POINT('',(-15.25,14.,3.5));
#1579=DIRECTION('',(0.,-0.447213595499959,0.894427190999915));
#1580=DIRECTION('',(-1.,0.,0.));
#1581=AXIS2_PLACEMENT_3D('',#1578,#1579,#1580);
#1582=PLANE('',#1581);
#1583=ORIENTED_EDGE('',*,*,#1029,.F.);
#1584=ORIENTED_EDGE('',*,*,#71,.F.);
#1585=ORIENTED_EDGE('',*,*,#866,.F.);
#1586=ORIENTED_EDGE('',*,*,#1558,.F.);
#1587=EDGE_LOOP('',(#1583,#1584,#1585,#1586));
#1588=FACE_BOUND('',#1587,.T.);
#1589=ADVANCED_FACE('F631',(#1588),#1582,.F.);
#1590=CARTESIAN_POINT('',(-15.25,14.,3.5));
#1591=DIRECTION('',(0.,-0.447213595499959,0.894427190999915));
#1592=DIRECTION('',(-1.,0.,0.));
#1593=AXIS2_PLACEMENT_3D('',#1590,#1591,#1592);
#1594=PLANE('',#1593);
#1595=ORIENTED_EDGE('',*,*,#450,.F.);
#1596=ORIENTED_EDGE('',*,*,#139,.F.);
#1597=ORIENTED_EDGE('',*,*,#651,.F.);
#1598=ORIENTED_EDGE('',*,*,#1561,.F.);
#1599=EDGE_LOOP('',(#1595,#1596,#1597,#1598));
#1600=FACE_BOUND('',#1599,.T.);
#1601=ADVANCED_FACE('F637',(#1600),#1594,.F.);
#1602=CARTESIAN_POINT('',(-15.25,14.,7.5));
#1603=DIRECTION('',(0.,-0.44721359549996,-0.894427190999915));
#1604=DIRECTION('',(1.,0.,0.));
#1605=AXIS2_PLACEMENT_3D('',#1602,#1603,#1604);
#1606=PLANE('',#1605);
#1607=ORIENTED_EDGE('',*,*,#637,.F.);
#1608=ORIENTED_EDGE('',*,*,#108,.F.);
#1609=ORIENTED_EDGE('',*,*,#480,.F.);
#1610=ORIENTED_EDGE('',*,*,#1552,.F.);
#1611=EDGE_LOOP('',(#1607,#1608,#1609,#1610));
#1612=FACE_BOUND('',#1611,.T.);
#1613=ADVANCED_FACE('F343',(#1612),#1606,.F.);
#1614=CARTESIAN_POINT('',(-15.25,14.,7.5));
#1615=DIRECTION('',(0.,-0.447213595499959,-0.894427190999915));
#1616=DIRECTION('',(1.,0.,0.));
#1617=AXIS2_PLACEMENT_3D('',#1614,#1615,#1616);
#1618=PLANE('',#1617);
#1619=ORIENTED_EDGE('',*,*,#836,.F.);
#1620=ORIENTED_EDGE('',*,*,#40,.F.);
#1621=ORIENTED_EDGE('',*,*,#1043,.F.);
#1622=ORIENTED_EDGE('',*,*,#1555,.F.);
#1623=EDGE_LOOP('',(#1619,#1620,#1621,#1622));
#1624=FACE_BOUND('',#1623,.T.);
#1625=ADVANCED_FACE('F44',(#1624),#1618,.F.);
#1626=CLOSED_SHELL('',(#58,#86,#126,#154,#177,#200,#240,#336,#367,#398,#538,#601,#762,#893,
#1054,#1082,#1110,#1132,#1163,#1175,#1196,#1217,#1229,#1250,#1271,#1283,#1294,#1305,#1322,#1339,
#1356,#1373,#1385,#1402,#1419,#1431,#1448,#1465,#1477,#1489,#1501,#1523,#1545,#1565,#1577,#1589,
#1601,#1613,#1625));
#1627=MANIFOLD_SOLID_BREP('B2',#1626);
#1628=ADVANCED_BREP_SHAPE_REPRESENTATION('',(#18,#1627),#14);
#1629=SHAPE_DEFINITION_REPRESENTATION(#9,#1628);
ENDSEC;
END-ISO-10303-21;
